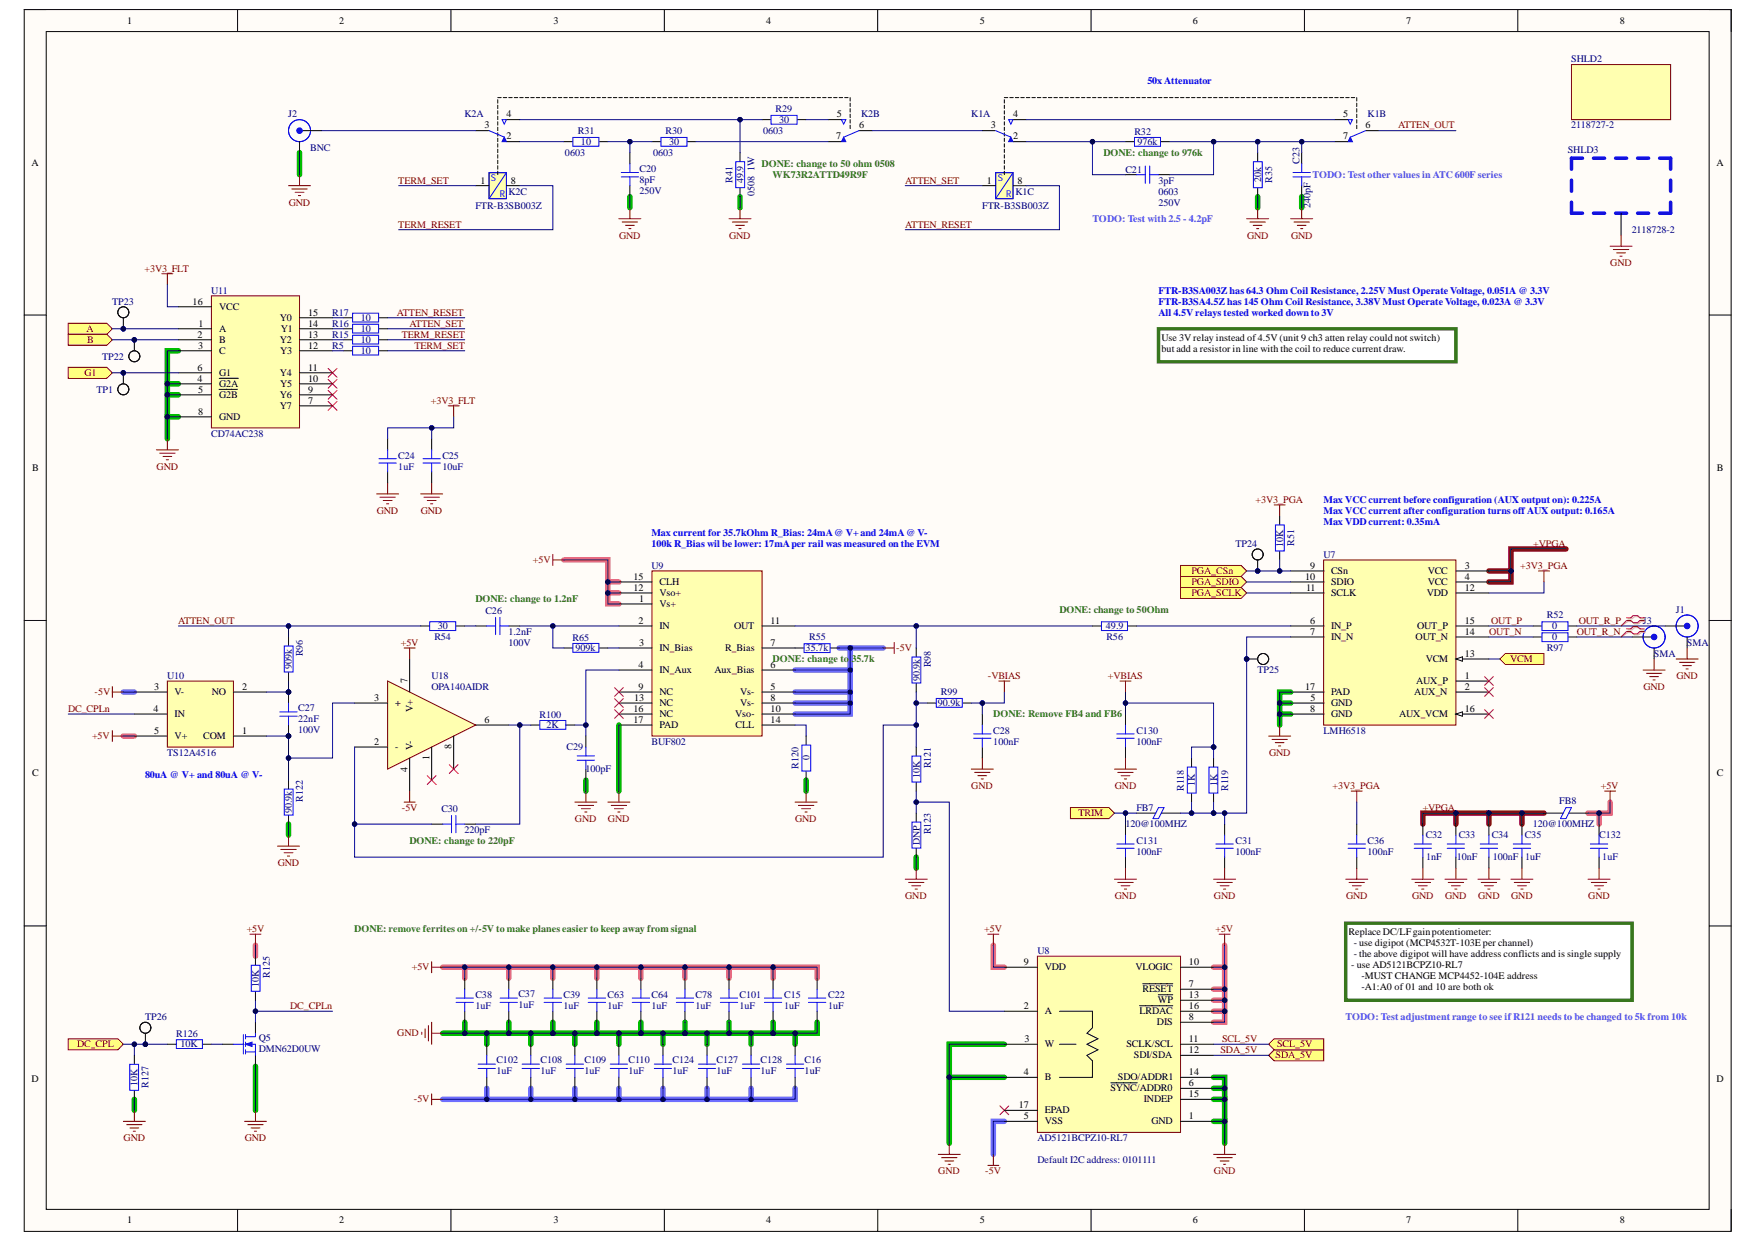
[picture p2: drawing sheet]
<svg xmlns="http://www.w3.org/2000/svg" width="297mm" height="210mm" viewBox="0 0 297 210" stroke-linecap="round" stroke-linejoin="round" font-family="sans-serif">
<defs><g id="words">
<g font-size="1.7">
<text x="21.5" y="4">1</text>
<text x="57.4" y="4">2</text>
<text x="93.6" y="4">3</text>
<text x="129.5" y="4">4</text>
<text x="165.6" y="4">5</text>
<text x="201.7" y="4">6</text>
<text x="237.7" y="4">7</text>
<text x="273.8" y="4">8</text>
<text x="81.9" y="21.7">3</text>
<text x="85.6" y="23.6">2</text>
<text x="85.6" y="19.9">4</text>
<text x="141.4" y="23.6">7</text>
<text x="141.5" y="19.9">5</text>
<text x="145.3" y="21.7">6</text>
<text x="167.5" y="21.7">3</text>
<text x="171.3" y="23.6">2</text>
<text x="171.3" y="19.9">4</text>
<text x="227.1" y="19.9">5</text>
<text x="227.1" y="23.6">7</text>
<text x="230.9" y="21.7">6</text>
<text x="5.3" y="28">A</text>
<text x="290.2" y="28">A</text>
<text x="81.2" y="31">1</text>
<text x="86.4" y="31">8</text>
<text x="166.8" y="31">1</text>
<text x="172" y="31">8</text>
<text x="32.6" y="51.5">16</text>
<text x="37.1" y="52.4">VCC</text>
<text x="52.1" y="53.3">15</text>
<text x="33.4" y="57.1">2</text>
<text x="33.5" y="58.9">3</text>
<text x="33.6" y="55.2">1</text>
<text x="37.1" y="56.1">A</text>
<text x="37.1" y="58">B</text>
<text x="37.1" y="59.8">C</text>
<text x="47.3" y="58">Y2</text>
<text x="47.3" y="54.3">Y0</text>
<text x="47.4" y="59.8">Y3</text>
<text x="47.5" y="56.1">Y1</text>
<text x="52.1" y="58.9">12</text>
<text x="52.1" y="57.1">13</text>
<text x="52.1" y="55.2">14</text>
<text x="196.4" y="57.6">Use 3V relay instead of4.5V (unit 9 ch3 atten relay could not switch)</text>
<text x="196.4" y="59.4">but add a resistor in line with the coil to reduce current draw.</text>
<text x="33.4" y="64.5">4</text>
<text x="33.4" y="62.6">6</text>
<text x="37.1" y="65.4">G2A</text>
<text x="37.1" y="63.6">G1</text>
<text x="47.3" y="63.6">Y4</text>
<text x="47.4" y="65.4">Y5</text>
<text x="52.1" y="64.5">10</text>
<text x="52.1" y="62.6">11</text>
<text x="33.5" y="66.3">5</text>
<text x="33.5" y="70.1">8</text>
<text x="37.1" y="67.3">G2B</text>
<text x="37.1" y="71">GND</text>
<text x="47.3" y="69.1">Y7</text>
<text x="47.3" y="67.3">Y6</text>
<text x="52.1" y="68.2">7</text>
<text x="52.1" y="66.3">9</text>
<text x="5.4" y="79.6">B</text>
<text x="290.3" y="79.6">B</text>
<text x="107.1" y="99.8">12</text>
<text x="107.1" y="98">15</text>
<text x="108" y="101.7">1</text>
<text x="111.5" y="100.8">Vso+</text>
<text x="111.5" y="98.9">CLH</text>
<text x="220.6" y="98">10</text>
<text x="220.8" y="99.8">11</text>
<text x="221.5" y="96.1">9</text>
<text x="225" y="97">CSn</text>
<text x="225" y="98.9">SDIO</text>
<text x="225" y="100.8">SCLK</text>
<text x="241.2" y="100.8">VDD</text>
<text x="241.4" y="97">VCC</text>
<text x="241.4" y="98.9">VCC</text>
<text x="247.6" y="99.8">12</text>
<text x="247.6" y="96.1">3</text>
<text x="247.6" y="98">4</text>
<text x="107.9" y="105.4">2</text>
<text x="111.5" y="102.6">Vs+</text>
<text x="111.5" y="106.3">IN</text>
<text x="124.1" y="106.3">OUT</text>
<text x="130.3" y="105.4">11</text>
<text x="221.5" y="105.4">6</text>
<text x="221.5" y="107.3">7</text>
<text x="225" y="106.3">IN_P</text>
<text x="239.6" y="106.3">OUT_P</text>
<text x="247.6" y="107.3">14</text>
<text x="247.6" y="105.4">15</text>
<text x="107.9" y="112.8">4</text>
<text x="108" y="109.1">3</text>
<text x="111.5" y="110.1">IN_Bias</text>
<text x="111.5" y="113.8">IN_Aux</text>
<text x="120.8" y="113.8">Aux_Bias</text>
<text x="122.6" y="110.1">R_Bias</text>
<text x="130.3" y="112.8">6</text>
<text x="130.3" y="109.1">7</text>
<text x="225" y="108.2">IN_N</text>
<text x="239.3" y="108.2">OUT_N</text>
<text x="241" y="111.9">VCM</text>
<text x="247.6" y="111">13</text>
<text x="26.1" y="116.6">3</text>
<text x="29.5" y="117.5">V-</text>
<text x="35.8" y="117.5">NO</text>
<text x="40.9" y="116.6">2</text>
<text x="63.3" y="118.4">3</text>
<text x="66.8" y="119.4">+</text>
<text x="68.9" y="115.5" transform="rotate(-90 68.9 115.5)">7</text>
<text x="107.2" y="118.4">13</text>
<text x="107.9" y="116.6">9</text>
<text x="111.5" y="117.5">NC</text>
<text x="111.5" y="119.4">NC</text>
<text x="125.1" y="117.5">Vs-</text>
<text x="125.1" y="119.4">Vs-</text>
<text x="130.3" y="116.6">5</text>
<text x="130.3" y="118.4">8</text>
<text x="220.6" y="116.6">17</text>
<text x="221.6" y="118.4">5</text>
<text x="225" y="119.4">GND</text>
<text x="225" y="117.5">PAD</text>
<text x="239.1" y="117.5">AUX_N</text>
<text x="239.4" y="115.6">AUX_P</text>
<text x="247.6" y="114.7">1</text>
<text x="247.6" y="116.6">2</text>
<text x="26" y="120.3">4</text>
<text x="26.1" y="124">5</text>
<text x="29.5" y="124.9">V+</text>
<text x="29.5" y="121.2">IN</text>
<text x="34.3" y="124.9">COM</text>
<text x="40.9" y="124">1</text>
<text x="63.3" y="125.9">2</text>
<text x="69.8" y="120.4" transform="rotate(-90 69.8 120.4)">V+</text>
<text x="81.9" y="122.1">6</text>
<text x="107.1" y="120.3">16</text>
<text x="107.1" y="122.1">17</text>
<text x="111.5" y="121.2">NC</text>
<text x="111.5" y="123.1">PAD</text>
<text x="124.3" y="121.2">Vso-</text>
<text x="124.4" y="123.1">CLL</text>
<text x="130.3" y="120.3">10</text>
<text x="130.3" y="122.1">14</text>
<text x="221.5" y="120.3">8</text>
<text x="225" y="121.2">GND</text>
<text x="236.5" y="121.2">AUX_VCM</text>
<text x="247.6" y="120.3">16</text>
<text x="5.4" y="131.2">C</text>
<text x="66.8" y="126.8">-</text>
<text x="68.9" y="130.4" transform="rotate(-90 68.9 130.4)">4</text>
<text x="69.8" y="126.8" transform="rotate(-90 69.8 126.8)">V-</text>
<text x="72.6" y="128.4" transform="rotate(-90 72.6 128.4)">1</text>
<text x="76.3" y="126.6" transform="rotate(-90 76.3 126.6)">8</text>
<text x="290.3" y="131.2">C</text>
<text x="228" y="158.1">Replace DC/LFgainpotentiometer:</text>
<text x="228.9" y="159.9">- use digipot (MCP4532T-103E per channel)</text>
<text x="228.9" y="161.8">- the above digipot will have address conflicts and is single supply</text>
<text x="173.1" y="163.1">9</text>
<text x="176.6" y="164">VDD</text>
<text x="192" y="164">VLOGIC</text>
<text x="193.1" y="167.7">RESET</text>
<text x="201" y="166.8">7</text>
<text x="201" y="163.1">10</text>
<text x="228.4" y="163.6">- use AD5121BCPZ10-RL7</text>
<text x="230.2" y="165.5">-MUST CHANGE MCP4452-104E address</text>
<text x="230.2" y="167.4">-A1:A0 of 01 and 10 are both ok</text>
<text x="173.1" y="170.5">2</text>
<text x="176.6" y="171.4">A</text>
<text x="192.6" y="171.4">LRDAC</text>
<text x="195.6" y="173.3">DIS</text>
<text x="195.8" y="169.6">WP</text>
<text x="201" y="172.4">8</text>
<text x="201" y="168.6">13</text>
<text x="201" y="170.5">16</text>
<text x="173.2" y="176.1">3</text>
<text x="176.6" y="177">W</text>
<text x="190.4" y="177">SCLK/SCL</text>
<text x="191.7" y="178.9">SDI/SDA</text>
<text x="201" y="176.1">11</text>
<text x="201" y="177.9">12</text>
<text x="5.3" y="182.8">D</text>
<text x="173.1" y="181.7">4</text>
<text x="176.6" y="182.6">B</text>
<text x="187.7" y="184.4">SYNC/ADDR0</text>
<text x="189" y="182.6">SDO/ADDR1</text>
<text x="201" y="183.5">6</text>
<text x="201" y="181.7">14</text>
<text x="201" y="185.4">15</text>
<text x="290.2" y="182.8">D</text>
<text x="172.2" y="187.2">17</text>
<text x="173.1" y="189.1">5</text>
<text x="176.6" y="190">VSS</text>
<text x="176.6" y="188.2">EPAD</text>
<text x="193.4" y="186.3">INDEP</text>
<text x="194.7" y="190">GND</text>
<text x="201" y="189.1">1</text>
<text x="21.5" y="206.8">1</text>
<text x="57.4" y="206.8">2</text>
<text x="93.6" y="206.8">3</text>
<text x="129.5" y="206.8">4</text>
<text x="165.6" y="206.8">5</text>
<text x="201.7" y="206.8">6</text>
<text x="237.7" y="206.8">7</text>
<text x="273.8" y="206.8">8</text>
</g>
<g font-size="1.7" fill="#000080">
<text x="265.6" y="10.6">SHLD2</text>
<text x="48.7" y="19.9">J2</text>
<text x="78.5" y="19.9">K2A</text>
<text x="97.7" y="22.6">R31</text>
<text x="112.5" y="22.6">R30</text>
<text x="129" y="22.6">0603</text>
<text x="131.1" y="18.9">R29</text>
<text x="131.7" y="20.8">30</text>
<text x="145.6" y="19.9">K2B</text>
<text x="164.2" y="19.9">K1A</text>
<text x="191.8" y="22.8">R32</text>
<text x="231.2" y="19.9">K1B</text>
<text x="265.6" y="21.7">2118727-2</text>
<text x="52.5" y="25.4">BNC</text>
<text x="95.5" y="26.4">0603</text>
<text x="98.2" y="24.5">10</text>
<text x="108.1" y="29">C20</text>
<text x="110.4" y="26.4">0603</text>
<text x="113.1" y="24.5">30</text>
<text x="127.6" y="28.9" transform="rotate(-90 127.6 28.9)">1W</text>
<text x="190.3" y="29.2">C21</text>
<text x="192.3" y="24.5">976k</text>
<text x="219.7" y="27.6" transform="rotate(-90 219.7 27.6)">C23</text>
<text x="265.1" y="25.8">SHLD3</text>
<text x="80.4" y="35.2">FTR-B3SB003Z</text>
<text x="86" y="32.9">K2C</text>
<text x="108.1" y="32.7">250V</text>
<text x="108.1" y="30.8">8pF</text>
<text x="123.9" y="30.8" transform="rotate(-90 123.9 30.8)">R41</text>
<text x="125.7" y="30.9" transform="rotate(-90 125.7 30.9)">49.9</text>
<text x="127.6" y="33" transform="rotate(-90 127.6 33)">0508</text>
<text x="166.1" y="35.2">FTR-B3SB003Z</text>
<text x="171.7" y="32.9">K1C</text>
<text x="195.8" y="32.9">0603</text>
<text x="195.8" y="34.7">250V</text>
<text x="195.8" y="31">3pF</text>
<text x="213.2" y="30.8" transform="rotate(-90 213.2 30.8)">20k</text>
<text x="215.1" y="30.8" transform="rotate(-90 215.1 30.8)">R35</text>
<text x="221.6" y="35.1" transform="rotate(-90 221.6 35.1)">240pF</text>
<text x="275.9" y="39.4">2118728-2</text>
<text x="19" y="51.5">TP23</text>
<text x="35.7" y="49.6">U11</text>
<text x="56.2" y="53.3">R17</text>
<text x="56.2" y="58.9">R5</text>
<text x="56.2" y="57.1">R15</text>
<text x="56.2" y="55.2">R16</text>
<text x="61" y="59.8">10</text>
<text x="61" y="58">10</text>
<text x="61" y="56.1">10</text>
<text x="61" y="54.3">10</text>
<text x="17.3" y="60.8">TP22</text>
<text x="16.3" y="66.3">TP1</text>
<text x="35.7" y="73.8">CD74AC238</text>
<text x="67.3" y="77.5">C24</text>
<text x="74.8" y="77.5">C25</text>
<text x="67.3" y="79.4">1uF</text>
<text x="74.8" y="79.4">10uF</text>
<text x="208.9" y="92.4">TP24</text>
<text x="216.9" y="92.4" transform="rotate(-90 216.9 92.4)">10K</text>
<text x="218.8" y="92.2" transform="rotate(-90 218.8 92.2)">R51</text>
<text x="223.8" y="94.2">U7</text>
<text x="110.1" y="96.1">U9</text>
<text x="74" y="106.3">30</text>
<text x="82.1" y="103.7">C26</text>
<text x="86" y="107.3">1.2nF</text>
<text x="187" y="106.3">49.9</text>
<text x="261.5" y="104.5">R52</text>
<text x="262.4" y="106.3">0</text>
<text x="277.7" y="105.4">J3</text>
<text x="283.3" y="103.5">J1</text>
<text x="49.3" y="113.1" transform="rotate(-90 49.3 113.1)">909k</text>
<text x="51.2" y="110.9" transform="rotate(-90 51.2 110.9)">R96</text>
<text x="73.4" y="108.2">R54</text>
<text x="86" y="109.1">100V</text>
<text x="96.8" y="108.4">R65</text>
<text x="97.3" y="110.1">909k</text>
<text x="136.2" y="110.1">35.7k</text>
<text x="136.8" y="108.2">R55</text>
<text x="157.4" y="112.8" transform="rotate(-90 157.4 112.8)">R98</text>
<text x="187" y="108.2">R56</text>
<text x="212.6" y="113.8">TP25</text>
<text x="261.5" y="110.1">R97</text>
<text x="262.4" y="108.2">0</text>
<text x="279.6" y="111">SMA</text>
<text x="285.2" y="109.1">SMA</text>
<text x="28.3" y="114.7">U10</text>
<text x="72.9" y="114.7">U18</text>
<text x="72.9" y="116.6">OPA140AIDR</text>
<text x="155.5" y="115.1" transform="rotate(-90 155.5 115.1)">90.9k</text>
<text x="158.5" y="119.4">90.9k</text>
<text x="159" y="117.5">R99</text>
<text x="50.4" y="123.8">100V</text>
<text x="50.4" y="120.1">C27</text>
<text x="50.4" y="122">22nF</text>
<text x="91.2" y="121.4">R100</text>
<text x="92.4" y="123.1">2K</text>
<text x="110.1" y="125.9">BUF802</text>
<text x="167.9" y="124">C28</text>
<text x="167.9" y="125.9">100nF</text>
<text x="192.1" y="124">C130</text>
<text x="192.1" y="125.9">100nF</text>
<text x="223.8" y="124">LMH6518</text>
<text x="28.3" y="127.7">TS12A4516</text>
<text x="95.8" y="126.8">C29</text>
<text x="99" y="130.5">100pF</text>
<text x="135" y="129.9" transform="rotate(-90 135 129.9)">R120</text>
<text x="136.9" y="128.5" transform="rotate(-90 136.9 128.5)">0</text>
<text x="155.5" y="131.4" transform="rotate(-90 155.5 131.4)">10K</text>
<text x="157.4" y="129.8" transform="rotate(-90 157.4 129.8)">R121</text>
<text x="49.3" y="137.4" transform="rotate(-90 49.3 137.4)">90.9k</text>
<text x="51.2" y="135.5" transform="rotate(-90 51.2 135.5)">R122</text>
<text x="74.6" y="137.3">C30</text>
<text x="192.1" y="137">FB7</text>
<text x="200.2" y="133.6" transform="rotate(-90 200.2 133.6)">R118</text>
<text x="202" y="132.9" transform="rotate(-90 202 132.9)">1K</text>
<text x="205.7" y="132.9" transform="rotate(-90 205.7 132.9)">1K</text>
<text x="207.6" y="133.6" transform="rotate(-90 207.6 133.6)">R119</text>
<text x="263.6" y="135.9">FB8</text>
<text x="78.5" y="140.7">220pF</text>
<text x="155.5" y="142.8" transform="rotate(-90 155.5 142.8)">DNP</text>
<text x="157.4" y="141" transform="rotate(-90 157.4 141)">R123</text>
<text x="190.3" y="139.8">120@100MHZ</text>
<text x="192.1" y="142.6">C131</text>
<text x="208.9" y="142.6">C31</text>
<text x="231.2" y="142.6">C36</text>
<text x="241" y="141.7">C32</text>
<text x="246.6" y="141.7">C33</text>
<text x="252.2" y="141.7">C34</text>
<text x="257.8" y="141.7">C35</text>
<text x="259.1" y="139.8">120@100MHZ</text>
<text x="270.4" y="141.7">C132</text>
<text x="192.1" y="144.5">100nF</text>
<text x="208.9" y="144.5">100nF</text>
<text x="231.2" y="144.5">100nF</text>
<text x="241.1" y="145.4">1nF</text>
<text x="246.3" y="145.4">10nF</text>
<text x="252.4" y="145.4">100nF 1uF</text>
<text x="270.9" y="145.4">1uF</text>
<text x="175.4" y="161.2">U8</text>
<text x="43.7" y="166.8" transform="rotate(-90 43.7 166.8)">10K</text>
<text x="45.6" y="165.3" transform="rotate(-90 45.6 165.3)">R125</text>
<text x="24.5" y="172.4">TP26</text>
<text x="80.4" y="168.6">C38</text>
<text x="80.4" y="170.5">1uF</text>
<text x="87.6" y="168.5">C37</text>
<text x="87.6" y="170.3">1uF</text>
<text x="95.3" y="168.6">C39</text>
<text x="95.3" y="170.5">1uF</text>
<text x="102.7" y="168.6">C63</text>
<text x="102.7" y="170.5">1uF</text>
<text x="110.1" y="168.6">C64</text>
<text x="110.1" y="170.5">1uF</text>
<text x="117.6" y="168.6">C78</text>
<text x="117.6" y="170.5">1uF</text>
<text x="125" y="168.6">C101</text>
<text x="125" y="170.5">1uF</text>
<text x="132.6" y="168.6">C15</text>
<text x="132.6" y="170.5">1uF</text>
<text x="140" y="168.6">C22</text>
<text x="140" y="170.5">1uF</text>
<text x="29.8" y="175.3">R126</text>
<text x="30.5" y="177">10K</text>
<text x="43.7" y="175.9">Q5</text>
<text x="43.7" y="177.8">DMN62D0UW</text>
<text x="83.9" y="179.6">C102</text>
<text x="91.4" y="179.6">C108</text>
<text x="98.8" y="179.6">C109</text>
<text x="106.3" y="179.6">C110</text>
<text x="113.7" y="179.6">C124</text>
<text x="121.1" y="179.6">C127</text>
<text x="128.6" y="179.6">C128</text>
<text x="136" y="179.6">C16</text>
<text x="23.3" y="183.5" transform="rotate(-90 23.3 183.5)">10K</text>
<text x="25.1" y="183.8" transform="rotate(-90 25.1 183.8)">R127</text>
<text x="83.9" y="181.5">1uF</text>
<text x="91.4" y="181.5">1uF</text>
<text x="98.8" y="181.5">1uF</text>
<text x="106.3" y="181.5">1uF</text>
<text x="113.7" y="181.5">1uF</text>
<text x="121.1" y="181.5">1uF</text>
<text x="128.6" y="181.5">1uF</text>
<text x="136" y="181.5">1uF</text>
<text x="175.4" y="192.8">AD5121BCPZ10-RL7</text>
<text x="175.4" y="196.5">Default I2C address: 0101111</text>
</g>
<g font-size="1.7" fill="#00f">
<text x="194" y="14.3">50x Attenuator</text>
<text x="195.8" y="49.6">FTR-B3SA003Z has 64.3 Ohm Coil Resistance, 2.25V Must Operate Voltage, 0.051A @ 3.3V</text>
<text x="195.8" y="51.5">FTR-B3SA4.5Z has 145 Ohm Coil Resistance, 3.38V Must Operate Voltage, 0.023A @ 3.3V</text>
<text x="195.8" y="53.3">All 4.5V relays tested worked down to 3V</text>
<text x="223.8" y="84.9">Max VCC current before configuration (AUX output on): 0.225A</text>
<text x="223.8" y="86.8">Max VCC current after configuration turns offAUX output: 0.165A</text>
<text x="223.8" y="88.7">Max VDD current: 0.35mA</text>
<text x="110.1" y="90.5">Max current for 35.7kOhm R_Bias: 24mA@ V+ and 24mA@ V-</text>
<text x="110.1" y="92.4">100k R_Bias wil be lower: 17mAper rail was measured on the EVM</text>
<text x="24.5" y="131.4">80uA @ V+ and 80uA @ V-</text>
</g>
<g font-size="1.7" fill="#800000">
<text x="236.4" y="21.7">ATTEN_OUT</text>
<text x="48.8" y="34.7">GND</text>
<text x="67.3" y="31">TERM_SET</text>
<text x="153" y="31">ATTEN_SET</text>
<text x="67.3" y="38.5">TERM_RESET</text>
<text x="104.6" y="40.3">GND</text>
<text x="123.3" y="40.3">GND</text>
<text x="153" y="38.5">ATTEN_RESET</text>
<text x="210.8" y="40.3">GND</text>
<text x="218.3" y="40.3">GND</text>
<text x="24.4" y="45.9">+3V3_FLT</text>
<text x="272.2" y="45">GND</text>
<text x="67.1" y="53.3">ATTEN_RESET</text>
<text x="14.6" y="56.1">A</text>
<text x="14.7" y="58">B</text>
<text x="67.9" y="57.1">TERM_RESET</text>
<text x="69.2" y="55.2">ATTEN_SET</text>
<text x="70" y="58.9">TERM_SET</text>
<text x="14.3" y="63.6">G1</text>
<text x="72.8" y="68.2">+3V3_FLT</text>
<text x="26.5" y="79.4">GND</text>
<text x="63.7" y="86.8">GND</text>
<text x="71.1" y="86.8">GND</text>
<text x="212.3" y="84.9">+3V3_PGA</text>
<text x="90.1" y="95.2">+5V</text>
<text x="259.2" y="92.4">+VPGA</text>
<text x="201.4" y="97">PGA_CSn</text>
<text x="201.4" y="100.8">PGA_SCLK</text>
<text x="201.4" y="98.9">PGA_SDIO</text>
<text x="257" y="96.1">+3V3_PGA</text>
<text x="30.1" y="105.4">ATTEN_OUT</text>
<text x="251.8" y="107.3">OUT_N</text>
<text x="252.1" y="105.4">OUT_P</text>
<text x="266.6" y="107.3">OUT_R_N</text>
<text x="266.9" y="105.4">OUT_R_P</text>
<text x="67.8" y="109.1">+5V</text>
<text x="151.5" y="110.1">-5V</text>
<text x="255.3" y="111.9">VCM</text>
<text x="16" y="117.5">-5V</text>
<text x="167" y="114.7">-VBIAS</text>
<text x="187.3" y="114.7">+VBIAS</text>
<text x="277.8" y="116.6">GND</text>
<text x="283.4" y="114.7">GND</text>
<text x="11.5" y="120.3">DC_CPLn</text>
<text x="15.6" y="124.9">+5V</text>
<text x="214.5" y="127.7">GND</text>
<text x="67.9" y="137">-5V</text>
<text x="164.2" y="133.3">GND</text>
<text x="182.3" y="137.9">TRIM</text>
<text x="188.5" y="133.3">GND</text>
<text x="225.3" y="133.3">+3V3_PGA</text>
<text x="240.5" y="137">+VPGA</text>
<text x="270.6" y="133.3">+5V</text>
<text x="97.2" y="138.9">GND</text>
<text x="102.8" y="138.9">GND</text>
<text x="134.4" y="138.9">GND</text>
<text x="47" y="146.3">GND</text>
<text x="153" y="151.9">GND</text>
<text x="188.5" y="151.9">GND</text>
<text x="205.2" y="151.9">GND</text>
<text x="227.6" y="151.9">GND</text>
<text x="238.7" y="151.9">GND</text>
<text x="244.3" y="151.9">GND</text>
<text x="249.9" y="151.9">GND</text>
<text x="255.5" y="151.9">GND</text>
<text x="268.5" y="151.9">GND</text>
<text x="41.7" y="157.5">+5V</text>
<text x="166.4" y="157.5">+5V</text>
<text x="205.5" y="157.5">+5V</text>
<text x="69.6" y="164">+5V</text>
<text x="49.1" y="170.5">DC_CPLn</text>
<text x="13" y="177">DC_CPL</text>
<text x="67.2" y="175.1">GND</text>
<text x="206.3" y="177.9">SDA_5V</text>
<text x="206.6" y="176.1">SCL_5V</text>
<text x="215.6" y="178.9">SDA_5V</text>
<text x="215.9" y="177">SCL_5V</text>
<text x="70" y="186.3">-5V</text>
<text x="20.9" y="192.8">GND</text>
<text x="41.4" y="192.8">GND</text>
<text x="158.6" y="198.4">GND</text>
<text x="166.6" y="198.4">-5V</text>
<text x="205.2" y="198.4">GND</text>
</g>
<g font-size="1.7" fill="#38761d">
<text x="128.8" y="28.2">DONE: change to 50 ohm 0508</text>
<text x="186.5" y="26.4">DONE: change to 976k</text>
<text x="130.6" y="30.1">WK73R2ATTD49R9F</text>
<text x="80.4" y="101.7">DONE: change to 1.2nF</text>
<text x="179.1" y="103.5">DONE: change to 50Ohm</text>
<text x="130.6" y="111.9">DONE: change to 35.7k</text>
<text x="167.9" y="121.2">DONE: Remove FB4 and FB6</text>
<text x="69.2" y="142.6">DONE: change to 220pF</text>
<text x="59.9" y="157.5">DONE: remove ferrites on +/-5V to make planes easier to keep away from signal</text>
</g>
<g font-size="1.7" fill="#90f">
<text x="221.9" y="30.1">TODO: Test other values in ATC 600F series</text>
<text x="184.7" y="37.5">TODO: Test with 2.5 - 4.2pF</text>
<text x="227.5" y="172.4">TODO: Test adjustment range to see ifR121 needs to be changed to 5k from 10k</text>
</g>
<g font-size="1.6" fill="#00f">
<text x="83" y="30.6">S</text>
<text x="84.5" y="33.2">R</text>
<text x="168.7" y="30.6">S</text>
<text x="170.1" y="33.2">R</text>
</g>
</g></defs>
<path d="M4.1 1.6h288.6v206.5h-288.6z" fill-rule="evenodd" fill="#fffcf8"/>
<path d="M4.1 1.6h288.6v206.5h-288.6z" fill="none" stroke="#000" stroke-width=".17"/>
<path d="M7.8 5.3h281.2v199.1h-281.2z" fill-rule="evenodd" fill="#fffcf8"/>
<g fill="none" stroke="#000" stroke-width=".17">
<path d="M4.1 1.6h3.7M7.8 5.3h281.2v199.1h-281.2zM40.2 1.6v3.7M76.2 1.6v3.7M112.3 1.6v3.7M148.4 1.6v3.7M184.5 1.6v3.7M220.5 1.6v3.7M256.6 1.6v3.7M289 1.6h3.7v3.7M274.1 36v3.8M4.1 53.2h3.7"/>
<path d="M289 53.2h3.7M4.1 104.9h3.7M289 104.9h3.7M4.1 156.5h3.7M289 156.5h3.7M40.2 204.4v3.7M76.2 204.4v3.7M112.3 204.4v3.7M148.4 204.4v3.7M184.5 204.4v3.7M220.5 204.4v3.7M256.6 204.4v3.7"/>
<path d="M292.7 204.4v3.7"/>
</g>
<g fill="none" stroke="#00be00" stroke-width=".93">
<path d="M50.6 25.8v3.7M106.5 33.2v1.9M125.1 33.2v1.9M212.6 33.2v1.9M220.1 33.2v1.9M30.2 59.3h-1.9v5.6M28.3 66.7h1.9M30.2 70.4h-1.9v3.8M30.2 64.9h-1.9v5.5M216.3 118.8h1.9M218.2 117h-1.9v3.7h1.9M48.8 139.3v1.8"/>
<path d="M99 131.8v1.9M104.6 122.5v11.2M136.3 131.8v1.9M216.3 120.7v1.8M154.9 144.9v1.8M74.8 174.6h3.8M78.6 172.8v1.8h7.4M82.3 174.6v1.9M86 174.6h7.5M86 172.8v1.8M89.7 174.6v1.9M93.5 174.6h7.4"/>
<path d="M93.5 172.8v1.8M97.2 174.6v1.9M100.9 174.6h7.5M100.9 172.8v1.8M104.6 174.6v1.9M108.4 174.6h7.4M108.4 172.8v1.8M112.1 174.6v1.9M115.8 172.8v1.8M119.5 174.6v1.9M123.3 172.8v1.8h-7.5M123.3 174.6h7.4"/>
<path d="M127 174.6v1.9M130.7 172.8v1.8M134.4 174.6v1.9M138.1 172.8v1.8h-7.4M169.8 176.5h-9.3v16.7M22.7 185.8v1.9M43.2 180.2v7.5M160.5 182.1h9.3M205.2 189.5h1.8v3.7M205.2 185.8h1.8v3.7M205.2 182.1h1.8v3.7M205.2 183.9h1.8"/>
</g>
<path d="M251.7 96.5h3.7M264.7 92.8h-9.3v5.6h-3.7M246.1 137.4h-5.6v1.9M251.7 137.4h-5.6v1.9M257.3 137.4v1.9M261 137.4h-9.3v1.9" fill="none" stroke="#a50021" stroke-width=".93"/>
<g fill="none" stroke="#ff6e6e" stroke-width=".93">
<path d="M95.3 94.6h7.5v7.5h1.8M102.8 98.4h1.8M102.8 100.2h1.8M20.8 124.4h1.9M270.3 137.4v1.9M272.2 135.6v1.8h-3.7M43.2 159.7v1.9M167.9 159.7v3.8h1.9M207 159.7v3.8h-1.8M74.8 163.5h3.8M78.6 165.3v-1.8h37.2v1.8M86 163.5v1.8"/>
<path d="M93.5 163.5v1.8M100.9 163.5v1.8M108.4 163.5v1.8M115.8 163.5h7.4v1.8M123.2 163.5h7.5v1.8M130.7 163.5h7.4v1.8M207 163.5v3.7h-1.8M207 167.2v1.8h-1.8M207 169v1.9h-1.8M207 170.9v1.9h-1.8"/>
</g>
<g fill="none" stroke="#6e6eff" stroke-width=".93">
<path d="M20.8 117h1.9M134.4 113.2h9.3v3.8h-9.3M134.4 118.8h9.3v1.9h-9.3M141.9 109.5h1.8v3.7M143.7 117v1.8M143.7 109.5h5.6M82.3 183.9v1.9M89.7 183.9v1.9M97.2 183.9v1.9M104.6 183.9v1.9M112.1 183.9v1.9M119.5 183.9v1.9"/>
<path d="M127 183.9v1.9M134.4 183.9v1.9h-59.6M169.8 189.5h-1.9v5.6"/>
</g>
<path d="M265.7 30.5v1.8M265.7 34.2v1.8h1.8M267.5 26.7h-1.8v1.9M269.4 36h1.9M269.4 26.7h1.9M273.1 36h1.9M273.1 26.7h1.9M276.9 36h1.8M276.9 26.7h1.8M280.6 26.7h1.8v1.9M282.4 34.2v1.8h-1.8M282.4 30.5v1.8" fill="none" stroke="#00f" stroke-width=".59"/>
<path d="M274.1 39.8v1.8M272.2 41.6h3.7M272.7 42.2h2.7M273.3 42.7h1.5M273.9 43.3h.3" fill="none" stroke="#800000" stroke-width=".17"/>
<path d="M265.7 10.9h16.7v9.3h-16.7z" fill-rule="evenodd" fill="#ffffb0"/>
<path d="M265.7 10.9h16.7v9.3h-16.7zM48.8 31.4h3.7M49.3 31.9h2.6M49.9 32.5h1.5M50.5 33.1h.3M50.6 29.5v1.9" fill="none" stroke="#800000" stroke-width=".17"/>
<circle cx="50.6" cy="22.1" r="1.86" fill="none" stroke="#00f" stroke-width=".17"/>
<path d="M50.6 22.1h3.8M50.6 23.9v1.9" fill="none" stroke="#000" stroke-width=".17"/>
<circle cx="50.6" cy="22.1" r=".46" fill="#00f"/>
<g fill="none" stroke="#00f" stroke-width=".17">
<path d="M186.2 105.1h4.4v1.5h-4.4z"/>
<circle cx="50.6" cy="22.1" r=".46"/>
</g>
<path d="M184.7 105.8h1.5M190.7 105.8h1.4" fill="none" stroke="#000" stroke-width=".17"/>
<path d="M223.8 94.6h22.3v27.9h-22.3z" fill-rule="evenodd" fill="#ffffb0"/>
<path d="M223.8 94.6h22.3v27.9h-22.3z" fill="none" stroke="#800000" stroke-width=".17"/>
<path d="M218.2 96.5h5.6M218.2 98.4h5.6M218.2 100.2h5.6M246.1 100.2h5.6M246.1 111.4h5.6" fill="none" stroke="#000" stroke-width=".17"/>
<path d="M246.1 111.4l1.1-.4v.8z" fill="#f8fcff"/>
<path d="M246.1 111.4l1.1-.4v.8zM246.1 107.7h5.6M246.1 105.8h5.6M246.1 115.1h5.6M246.1 117h5.6M246.1 120.7h5.6" fill="none" stroke="#000" stroke-width=".17"/>
<path d="M246.1 120.7l1.1-.4v.8z" fill="#f8fcff"/>
<path d="M246.1 96.5h5.6M246.1 98.4h5.6M218.2 118.8h5.6M218.2 117h5.6M218.2 105.8h5.6M218.2 107.7h5.6M218.2 120.7h5.6M246.1 120.7l1.1-.4v.8z" fill="none" stroke="#000" stroke-width=".17"/>
<path d="M199.6 95.6h10.2l1 .9-1 .9h-10.2z" fill-rule="evenodd" fill="#ffff80"/>
<path d="M199.6 95.6h10.2l1 .9-1 .9h-10.2z" fill="none" stroke="#800000" stroke-width=".17"/>
<path d="M216.3 87.2v1.5M216.3 93.2v1.4" fill="none" stroke="#000" stroke-width=".17"/>
<path d="M215.6 88.7h1.5v4.4h-1.5z" fill="none" stroke="#00f" stroke-width=".17"/>
<path d="M199.6 99.3h10.2l1 .9-1 .9h-10.2z" fill-rule="evenodd" fill="#ffff80"/>
<path d="M199.6 99.3h10.2l1 .9-1 .9h-10.2z" fill="none" stroke="#800000" stroke-width=".17"/>
<path d="M199.6 97.4h10.2l1 1-1 .9h-10.2z" fill-rule="evenodd" fill="#ffff80"/>
<path d="M199.6 97.4h10.2l1 1-1 .9h-10.2zM214.5 124.4h3.7M215 125h2.6M215.6 125.5h1.5M216.2 126.1h.3M216.3 122.5v1.9" fill="none" stroke="#800000" stroke-width=".17"/>
<path d="M253.6 111.4l.9-1h6.5v1.9h-6.5z" fill-rule="evenodd" fill="#ffff80"/>
<path d="M253.6 111.4l.9-1h6.5v1.9h-6.5z" fill="none" stroke="#800000" stroke-width=".17"/>
<path d="M251 114.4l1.5 1.4M251 116.2l1.5 1.5M251 119.9l1.5 1.5M252.5 114.4l-1.5 1.4M252.5 116.2l-1.5 1.5M252.5 119.9l-1.5 1.5" fill="none" stroke="#f00" stroke-width=".17"/>
<path d="M259.2 105.8h1.4M259.2 107.7h1.4M265.1 105.8h1.5M265.1 107.7h1.5" fill="none" stroke="#000" stroke-width=".17"/>
<path d="M260.7 105.1h4.4v1.5h-4.4zM260.7 106.9h4.4v1.5h-4.4z" fill="none" stroke="#00f" stroke-width=".17"/>
<circle cx="212.6" cy="96.5" r=".37" fill="#000080"/>
<circle cx="212.6" cy="96.5" r=".37" fill="none" stroke="#000080" stroke-width=".17"/>
<path d="M212.6 94.6v1.9" fill="none" stroke="#000" stroke-width=".17"/>
<circle cx="212.6" cy="96.5" r=".37" fill="#000080"/>
<circle cx="212.6" cy="96.5" r=".37" fill="none" stroke="#000080" stroke-width=".17"/>
<g fill="none" stroke="#000" stroke-width=".17">
<path d="M201.4 128.1v1.5M201.4 134.1v1.5M205.2 128.1v1.5M205.2 134.1v1.5M229.4 139.3v1.8M240.5 139.3v1.8M246.1 139.3v1.8M251.7 139.3v1.8M257.3 139.3v1.8M229.4 144.9v1.8M240.5 144.9v1.8M246.1 144.9v1.8"/>
<path d="M251.7 144.9v1.8M257.3 144.9v1.8"/>
<circle cx="212.6" cy="93.7" r=".93"/>
</g>
<g fill="none" stroke="#00f" stroke-width=".17">
<path d="M200.7 129.6h1.5v4.4h-1.5zM204.4 129.6h1.5v4.4h-1.5zM227.9 143.4h2.9M227.9 142.6h2.9M229.4 141.1v1.5M229.4 143.4v1.5M239.1 143.4h2.9M239.1 142.6h2.9M240.5 141.1v1.5M240.5 143.4v1.5M244.7 143.4h2.9M244.7 142.6h2.9"/>
<path d="M246.1 141.1v1.5M246.1 143.4v1.5M250.2 143.4h3M250.2 142.6h3M251.7 141.1v1.5M251.7 143.4v1.5M255.8 143.4h3M255.8 142.6h3M257.3 141.1v1.5M257.3 143.4v1.5"/>
</g>
<g fill="none" stroke="#800000" stroke-width=".17">
<path d="M271.3 133.7h1.8M272.2 133.7v1.9M227.5 148.6h3.7M228.1 149.1h2.6M228.6 149.7h1.5M229.2 150.3h.4M229.4 146.7v1.9M238.7 148.6h3.7M239.2 149.1h2.6M239.8 149.7h1.5M240.4 150.3h.3M240.5 146.7v1.9"/>
<path d="M244.3 148.6h3.7M244.8 149.1h2.6M245.4 149.7h1.5M245.9 150.3h.4M246.1 146.7v1.9M249.9 148.6h3.7M250.4 149.1h2.6M251 149.7h1.5M251.5 150.3h.4M251.7 146.7v1.9M255.4 148.6h3.8M256 149.1h2.6"/>
<path d="M256.6 149.7h1.5M257.1 150.3h.4M257.3 146.7v1.9"/>
</g>
<path d="M181 136.5h6.5l.9 .9-.9 .9h-6.5z" fill-rule="evenodd" fill="#ffff80"/>
<path d="M181 136.5h6.5l.9 .9-.9 .9h-6.5z" fill="none" stroke="#800000" stroke-width=".17"/>
<circle cx="210.8" cy="111.4" r=".38" fill="#000080"/>
<circle cx="210.8" cy="111.4" r=".38" fill="none" stroke="#000080" stroke-width=".17"/>
<path d="M210.8 111.4h1.8" fill="none" stroke="#000" stroke-width=".17"/>
<circle cx="210.8" cy="111.4" r=".38" fill="#000080"/>
<circle cx="210.8" cy="111.4" r=".38" fill="none" stroke="#000080" stroke-width=".17"/>
<g fill="none" stroke="#000" stroke-width=".17">
<path d="M207 139.3v1.8M207 144.9v1.8"/>
<circle cx="213.5" cy="111.4" r=".93"/>
<circle cx="213.6" cy="111.4" r=".93"/>
</g>
<path d="M205.6 142.6h2.9M205.6 143.4h2.9M207 141.1v1.5M207 143.4v1.5" fill="none" stroke="#00f" stroke-width=".17"/>
<path d="M215.4 85.3h1.9M216.3 85.3v1.9M260.1 96.5h1.9M261 96.5v1.9M228.4 133.7h1.9M229.4 133.7v1.9M205.2 148.6h3.7M205.7 149.1h2.6M206.3 149.7h1.5M206.8 150.3h.4M207 146.7v1.9" fill="none" stroke="#800000" stroke-width=".17"/>
<path d="M168.3 29.2h3v4.4h-3z" fill-rule="evenodd" fill="#ffffb0"/>
<path d="M168.3 29.2h3v4.4h-3z" fill="none" stroke="#800000" stroke-width=".17"/>
<path d="M171.3 29.2l-3 4.4M171.3 29.2h-3v4.4M171.3 29.2v4.4h-3" fill="none" stroke="#00f" stroke-width=".17"/>
<path d="M166.1 31.4h2.2M171.3 31.4h2.2" fill="none" stroke="#000" stroke-width=".17"/>
<path d="M11.5 56.5h6.6l.9 .9-.9 1h-6.6z" fill-rule="evenodd" fill="#ffff80"/>
<path d="M210.8 37h3.7M211.3 37.5h2.6M211.9 38.1h1.5M212.4 38.6h.4M212.6 35.1v1.9M218.2 37h3.7M218.8 37.5h2.6M219.3 38.1h1.5M219.9 38.6h.4M220.1 35.1v1.9M11.5 56.5h6.6l.9 .9-.9 1h-6.6z" fill="none" stroke="#800000" stroke-width=".17"/>
<g fill="none" stroke="#000" stroke-width=".17">
<path d="M169.8 16.8v.6M169.8 17.8v.6M169.8 18.7v.6M169.8 19.6v.6M169.8 16.5h.6M170.7 16.5h.6M171.7 16.5h.5M172.6 16.5h.6M173.5 16.5h.6M174.5 16.5h.5M175.4 16.5h.6M176.3 16.5h.6"/>
<path d="M177.2 16.5h.6M178.2 16.5h.6M179.1 16.5h.6M180 16.5h.6M181 16.5h.6M181.9 16.5h.6M182.8 16.5h.6M183.8 16.5h.5M184.7 16.5h.6M185.6 16.5h.6M186.6 16.5h.5M187.5 16.5h.6"/>
<path d="M188.4 16.5h.6M189.3 16.5h.6M190.3 16.5h.6M191.2 16.5h.6M192.1 16.5h.6M193.1 16.5h.5M194 16.5h.6M194.9 16.5h.6M195.9 16.5h.5M196.8 16.5h.6M197.7 16.5h.6M198.7 16.5h.5"/>
<path d="M199.6 16.5h.6M200.5 16.5h.6M201.4 16.5h.6M202.4 16.5h.6M203.3 16.5h.6M204.2 16.5h.6M205.2 16.5h.5M206.1 16.5h.6M207 16.5h.6M208 16.5h.5M208.9 16.5h.6M209.8 16.5h.6"/>
<path d="M210.8 16.5h.5M211.7 16.5h.6M212.6 16.5h.6M213.6 16.5h.5M214.5 16.5h.6M215.4 16.5h.6M216.3 16.5h.6M217.3 16.5h.6M218.2 16.5h.6M219.1 16.5h.6M220.1 16.5h.5M221 16.5h.6"/>
<path d="M221.9 16.5h.6M222.9 16.5h.5M223.8 16.5h.6M224.7 16.5h.6M225.6 16.5h.6M226.6 16.5h.6M227.5 16.5h.6M228.4 16.5h.6M229.4 16.5v.6M229.4 17.4v.6M229.4 18.4v.5M229.4 19.3v.6"/>
<path d="M166.1 22.1h2.2M169.8 20.6v.6M169.8 21.5v.6M169.8 22.4v.6M169.8 23.4v.5M169.8 24.3v.6M169.8 25.2v.6M169.8 26.1v.6M169.8 27.1v.6M169.8 28v.6M169.8 28.9v.6M190.3 23.9h1.4"/>
<path d="M190.3 29.5h1.8M195.9 29.5h1.8M196.3 23.9h1.4M212.6 25.8v1.5M212.6 31.8v1.4M220.1 25.8v1.9M220.1 31.4v1.8M229.4 20.2v.6M229.4 21.2v.5"/>
</g>
<path d="M168.3 22.1l2.6 1.1M191.8 23.2h4.4v1.5h-4.4zM192.1 29.5h1.5M193.6 28.1v2.9M194.4 29.5h1.5M194.4 28.1v2.9M211.9 27.3h1.5v4.4h-1.5zM218.6 29.9h2.9M218.6 29.2h2.9M220.1 27.7v1.5M220.1 29.9v1.5" fill="none" stroke="#00f" stroke-width=".17"/>
<path d="M170.9 23.2l.4 .7h-.8z" fill="#00f"/>
<path d="M170.5 20.2h.8l-.4 .8zM170.9 23.2l.4 .7h-.8zM227.9 20.2h.7l-.3 .8zM230.9 22.1l-2.6 1.1" fill="none" stroke="#00f" stroke-width=".17"/>
<path d="M171.3 23.9h2.2M171.3 20.2h2.2M230.9 22.1h2.2" fill="none" stroke="#000" stroke-width=".17"/>
<path d="M228.3 23.2l.3 .7h-.7z" fill="#00f"/>
<path d="M228.3 23.2l.3 .7h-.7z" fill="none" stroke="#00f" stroke-width=".17"/>
<path d="M225.6 20.2h2.2M225.6 23.9h2.2" fill="none" stroke="#000" stroke-width=".17"/>
<path d="M11.5 54.6h6.6l.9 1-.9 .9h-6.6z" fill-rule="evenodd" fill="#ffff80"/>
<path d="M104.6 37h3.8M105.2 37.5h2.6M105.7 38.1h1.5M106.3 38.6h.4M106.5 35.1v1.9M11.5 54.6h6.6l.9 1-.9 .9h-6.6z" fill="none" stroke="#800000" stroke-width=".17"/>
<path d="M106.5 25.8v1.9M106.5 31.4v1.8" fill="none" stroke="#000" stroke-width=".17"/>
<path d="M105 29.2h3M105 29.9h3M106.5 27.7v1.5M106.5 29.9v1.5" fill="none" stroke="#00f" stroke-width=".17"/>
<path d="M82.7 29.2h2.9v4.4h-2.9z" fill-rule="evenodd" fill="#ffffb0"/>
<path d="M82.7 29.2h2.9v4.4h-2.9z" fill="none" stroke="#800000" stroke-width=".17"/>
<path d="M82.7 22.1l2.6 1.1M85.6 29.2l-2.9 4.4M85.6 29.2h-2.9v4.4M85.6 29.2v4.4h-2.9" fill="none" stroke="#00f" stroke-width=".17"/>
<g fill="none" stroke="#000" stroke-width=".17">
<path d="M84.2 16.8v.6M84.2 17.8v.6M84.2 18.7v.6M84.2 19.6v.6M84.2 16.5h.5M85.1 16.5h.6M86 16.5h.6M86.9 16.5h.6M87.9 16.5h.6M88.8 16.5h.6M89.7 16.5h.6M90.7 16.5h.5"/>
<path d="M91.6 16.5h.6M92.5 16.5h.6M93.5 16.5h.5M94.4 16.5h.6M95.3 16.5h.6M96.3 16.5h.5M97.2 16.5h.6M98.1 16.5h.6M99 16.5h.6M100 16.5h.6M100.9 16.5h.6M101.8 16.5h.6"/>
<path d="M102.8 16.5h.5M103.7 16.5h.6M104.6 16.5h.6M105.6 16.5h.5M106.5 16.5h.6M107.4 16.5h.6M108.4 16.5h.5M109.3 16.5h.6M110.2 16.5h.6M111.1 16.5h.6M112.1 16.5h.6M113 16.5h.6"/>
<path d="M113.9 16.5h.6M114.9 16.5h.6M115.8 16.5h.6M116.7 16.5h.6M117.7 16.5h.5M118.6 16.5h.6M119.5 16.5h.6M120.5 16.5h.5M121.4 16.5h.6M122.3 16.5h.6M123.2 16.5h.6M124.2 16.5h.6"/>
<path d="M125.1 16.5h.6M126 16.5h.6M127 16.5h.6M127.9 16.5h.6M128.8 16.5h.6M129.8 16.5h.5M130.7 16.5h.6M131.6 16.5h.6M132.6 16.5h.5M133.5 16.5h.6M134.4 16.5h.6M135.3 16.5h.6"/>
<path d="M136.3 16.5h.6M137.2 16.5h.6M138.1 16.5h.6M139.1 16.5h.6M140 16.5h.6M140.9 16.5h.6M141.9 16.5h.5M142.8 16.5h.6M143.7 16.5v.6M143.7 17.4v.6M143.7 18.4v.5M143.7 19.3v.6"/>
<path d="M80.4 31.4h2.2M80.4 22.1h2.2M84.2 20.6v.6M84.2 21.5v.6M84.2 22.4v.6M84.2 23.4v.5M84.2 24.3v.6M84.2 25.2v.6M84.2 26.1v.6M84.2 27.1v.6M84.2 28v.6M84.2 28.9v.6"/>
<path d="M85.7 31.4h2.2M143.7 20.2v.6M143.7 21.2v.5"/>
</g>
<path d="M85.3 23.2l.3 .7h-.7z" fill="#00f"/>
<path d="M84.9 20.2h.7l-.3 .8zM85.3 23.2l.3 .7h-.7zM142.3 20.2h.7l-.4 .8zM145.2 22.1l-2.5 1.1" fill="none" stroke="#00f" stroke-width=".17"/>
<path d="M85.7 23.9h2.2M85.7 20.2h2.2M145.3 22.1h2.2" fill="none" stroke="#000" stroke-width=".17"/>
<path d="M142.6 23.2l.4 .7h-.7z" fill="#00f"/>
<path d="M130.4 19.5h4.4v1.5h-4.4zM96.8 23.2h4.4v1.5h-4.4zM124.4 27.3h1.5v4.4h-1.5zM142.6 23.2l.4 .7h-.7z" fill="none" stroke="#00f" stroke-width=".17"/>
<path d="M95.3 23.9h1.5M101.3 23.9h1.5M125.1 25.8v1.5M125.1 31.8v1.4M128.8 20.2h1.5M134.8 20.2h1.5M140 20.2h2.2M140 23.9h2.2" fill="none" stroke="#000" stroke-width=".17"/>
<path d="M123.2 37h3.8M123.8 37.5h2.6M124.4 38.1h1.5M124.9 38.6h.4M125.1 35.1v1.9M46.9 143h3.7M47.5 143.6h2.6M48 144.1h1.5M48.6 144.7h.4M48.8 141.1v1.9" fill="none" stroke="#800000" stroke-width=".17"/>
<path d="M65.5 115.1l14.9 7.4-14.9 7.5z" fill="#ffffb0"/>
<g fill="none" stroke="#800000" stroke-width=".17">
<path d="M65.5 115.1l14.9 7.4-14.9 7.5zM168.9 115.1h1.8M169.8 115.1v1.9M164.2 130h3.7M164.8 130.5h2.6M165.3 131.1h1.5M165.9 131.6h.4M166.1 128.1v1.9M153 148.6h3.8M153.6 149.1h2.6M154.2 149.7h1.4M154.7 150.3h.4"/>
<path d="M154.9 146.7v1.9"/>
</g>
<g fill="none" stroke="#000" stroke-width=".17">
<path d="M48.8 107.7v1.4M48.8 113.6v1.5M59.9 118.8h5.6M69.3 111.4v5.6M71.1 105.8h1.5M77.1 105.8h1.5M80.4 105.8h1.9M86 105.8h1.9M154.9 109.5v1.5M154.9 115.5v1.5M156.8 118.8h1.4M162.7 118.8h1.5"/>
<path d="M48.8 131.8v1.5M48.8 137.8v1.5M59.9 126.3h5.6M69.3 128.1v5.6M73 126.3v5.5M73 139.3h1.8M76.7 124.4v5.6M78.6 139.3h1.8M80.4 122.5h5.6M89.7 122.5h1.5M95.7 122.5h1.5M154.9 126.3v1.4"/>
<path d="M154.9 132.2v1.5M154.9 137.4v1.5M166.1 120.7v1.8M166.1 126.3v1.8M154.9 143.4v1.5M78.6 165.3v1.9M78.6 170.9v1.9M93.5 165.3v1.9M93.5 170.9v1.9M100.9 165.3v1.9M100.9 170.9v1.9M108.4 165.3v1.9"/>
<path d="M108.4 170.9v1.9M115.8 165.3v1.9M115.8 170.9v1.9"/>
</g>
<path d="M72.2 131.1l1.5 1.5M73.7 131.1l-1.5 1.5M76 129.2l1.4 1.5M77.4 129.2l-1.4 1.5" fill="none" stroke="#f00" stroke-width=".17"/>
<g fill="none" stroke="#00f" stroke-width=".17">
<path d="M48.1 109.2h1.4v4.4h-1.4zM72.6 105.1h4.4v1.5h-4.4zM82.3 105.8h1.5M83.8 104.3v3M84.5 105.8h1.5M84.5 104.3v3M154.2 111h1.5v4.4h-1.5zM158.3 118h4.4v1.5h-4.4zM48.1 133.4h1.4v4.4h-1.4zM74.8 139.3h1.5M76.3 137.8v2.9M77.1 139.3h1.5"/>
<path d="M77.1 137.8v2.9M91.3 121.8h4.4v1.4h-4.4zM154.2 127.8h1.5v4.4h-1.5zM154.2 138.9h1.5v4.4h-1.5zM164.6 124h2.9M164.6 124.8h2.9M166.1 122.5v1.5M166.1 124.8v1.5M77.1 168.7h2.9M77.1 169.4h2.9M78.6 167.2v1.5M78.6 169.4v1.5"/>
<path d="M92 168.7h2.9M92 169.4h2.9M93.5 167.2v1.5M93.5 169.4v1.5M99.4 168.7h3M99.4 169.4h3M100.9 167.2v1.5M100.9 169.4v1.5M106.9 168.7h2.9M106.9 169.4h2.9M108.4 167.2v1.5M108.4 169.4v1.5"/>
<path d="M114.3 168.7h3M114.3 169.4h3M115.8 167.2v1.5M115.8 169.4v1.5"/>
</g>
<path d="M110.2 96.5h18.6v27.9h-18.6z" fill-rule="evenodd" fill="#ffffb0"/>
<g fill="none" stroke="#800000" stroke-width=".17">
<path d="M110.2 96.5h18.6v27.9h-18.6zM97.2 135.6h3.7M97.7 136.1h2.6M98.3 136.7h1.5M98.9 137.2h.3M99 133.7v1.9M102.8 135.6h3.7M103.3 136.1h2.6M103.9 136.7h1.5M104.4 137.2h.4M104.6 133.7v1.9M134.4 135.6h3.7"/>
<path d="M135 136.1h2.6M135.5 136.7h1.5M136.1 137.2h.4M136.3 133.7v1.9M71.3 174.4v.4M71.9 173.9v1.5M72.4 173.3v2.6M73 162.5v1.9M73 172.8v3.7M73 163.5h1.8M73 174.6h1.8M73 184.9v1.8"/>
<path d="M73 185.8h1.8"/>
</g>
<g fill="none" stroke="#000" stroke-width=".17">
<path d="M104.6 98.4h5.6M95.3 109.5h1.5M101.3 109.5h1.5M104.6 102.1h5.6M104.6 105.8h5.6M104.6 109.5h5.6M104.6 113.2h5.6M104.6 117h5.6M104.6 118.8h5.6M104.6 100.2h5.6M128.8 105.8h5.6M128.8 109.5h7.1"/>
<path d="M128.8 113.2h5.6M128.8 117h5.6M128.8 118.8h5.6M140.4 109.5h1.5M99 124.4v1.9M99 130v1.8M104.6 120.7h5.6M104.6 122.5h5.6M128.8 120.7h5.6M128.8 122.5h5.6M136.3 124.4v1.5M136.3 130.4v1.4"/>
<path d="M43.2 161.6v1.5M43.2 167.6v1.4M86 165.3v1.9M86 170.9v1.9M89.7 176.5v1.9M97.2 176.5v1.9M104.6 176.5v1.9M112.1 176.5v1.9M89.7 182.1v1.8M97.2 182.1v1.8M104.6 182.1v1.8M112.1 182.1v1.8"/>
</g>
<path d="M103.9 116.2l1.5 1.5M103.9 118.1l1.5 1.5M103.9 119.9l1.5 1.5M105.4 116.2l-1.5 1.5M105.4 118.1l-1.5 1.5M105.4 119.9l-1.5 1.5" fill="none" stroke="#f00" stroke-width=".17"/>
<g fill="none" stroke="#00f" stroke-width=".17">
<path d="M96.8 108.7h4.4v1.5h-4.4zM135.9 108.8h4.4v1.5h-4.4zM97.6 128.5h2.9M97.6 127.8h2.9M99 126.3v1.5M99 128.5v1.5M135.6 125.9h1.5v4.4h-1.5zM42.5 163.1h1.5v4.4h-1.5zM84.5 169.4h3M84.5 168.7h3M86 167.2v1.5M86 169.4v1.5"/>
<path d="M88.3 179.8h2.9M89.7 178.4v1.4M95.7 179.8h3M97.2 178.4v1.4M103.2 179.8h2.9M104.6 178.4v1.4M110.6 179.8h2.9M112.1 178.4v1.4M88.3 180.6h2.9M89.7 180.6v1.5M95.7 180.6h3M97.2 180.6v1.5"/>
<path d="M103.2 180.6h2.9M104.6 180.6v1.5M110.6 180.6h2.9M112.1 180.6v1.5"/>
</g>
<circle cx="24.6" cy="176.5" r=".37" fill="#000080"/>
<circle cx="24.6" cy="176.5" r=".37" fill="none" stroke="#000080" stroke-width=".17"/>
<path d="M24.6 174.6v1.9" fill="none" stroke="#000" stroke-width=".17"/>
<circle cx="24.6" cy="176.5" r=".37" fill="#000080"/>
<circle cx="24.6" cy="176.5" r=".37" fill="none" stroke="#000080" stroke-width=".17"/>
<g fill="none" stroke="#000" stroke-width=".17">
<path d="M22.7 178.4v1.4M22.7 184.3v1.5"/>
<circle cx="24.6" cy="173.7" r=".93"/>
</g>
<path d="M21.9 179.9h1.5v4.4h-1.5z" fill="none" stroke="#00f" stroke-width=".17"/>
<path d="M20.9 189.5h3.7M21.4 190.1h2.6M22 190.6h1.5M22.5 191.2h.4M22.7 187.7v1.8" fill="none" stroke="#800000" stroke-width=".17"/>
<path d="M11.5 175.6h8.4l1 .9-1 .9h-8.4z" fill-rule="evenodd" fill="#ffff80"/>
<path d="M11.5 175.6h8.4l1 .9-1 .9h-8.4z" fill="none" stroke="#800000" stroke-width=".17"/>
<path d="M82.3 176.5v1.9M119.5 176.5v1.9M123.2 165.3v1.9M123.2 170.9v1.9M127 176.5v1.9M82.3 182.1v1.8M119.5 182.1v1.8M127 182.1v1.8" fill="none" stroke="#000" stroke-width=".17"/>
<g fill="none" stroke="#00f" stroke-width=".17">
<path d="M80.8 179.8h3M82.3 178.4v1.4M118.1 179.8h2.9M119.5 178.4v1.4M121.8 169.4h2.9M121.8 168.7h2.9M123.2 167.2v1.5M123.2 169.4v1.5M125.5 179.8h2.9M127 178.4v1.4M80.8 180.6h3M82.3 180.6v1.5"/>
<path d="M118.1 180.6h2.9M119.5 180.6v1.5M125.5 180.6h2.9M127 180.6v1.5"/>
</g>
<path d="M28.3 115.1h11.2v11.2h-11.2z" fill-rule="evenodd" fill="#ffffb0"/>
<path d="M28.3 115.1h11.2v11.2h-11.2z" fill="none" stroke="#800000" stroke-width=".17"/>
<path d="M22.7 117h5.6M39.5 117h5.5M22.7 124.4h5.6M22.7 120.7h5.6M39.5 124.4h5.5" fill="none" stroke="#000" stroke-width=".17"/>
<circle cx="48.8" cy="117" r=".37" fill="#000080"/>
<circle cx="48.8" cy="117" r=".37" fill="none" stroke="#000080" stroke-width=".17"/>
<circle cx="48.8" cy="124.4" r=".37" fill="#000080"/>
<circle cx="48.8" cy="124.4" r=".37" fill="none" stroke="#000080" stroke-width=".17"/>
<path d="M48.8 117v1.8" fill="none" stroke="#000" stroke-width=".17"/>
<circle cx="48.8" cy="117" r=".37" fill="#000080"/>
<circle cx="48.8" cy="117" r=".37" fill="none" stroke="#000080" stroke-width=".17"/>
<path d="M48.8 122.5v1.9" fill="none" stroke="#000" stroke-width=".17"/>
<circle cx="48.8" cy="124.4" r=".37" fill="#000080"/>
<circle cx="48.8" cy="124.4" r=".37" fill="none" stroke="#000080" stroke-width=".17"/>
<path d="M48.8 118.8v1.5M47.3 120.3h2.9M47.3 121h2.9M48.8 121v1.5M39.5 176.5h1.6M41.1 174.8v3.3M41.5 175.2h1.7M41.5 176.5h1.7v1.9M41.5 177.8h1.7M41.5 174.8v.8M41.5 176.1v.8M41.5 177.4v.7" fill="none" stroke="#00f" stroke-width=".17"/>
<path d="M37.6 176.5h1.9M43.2 172.8v1.8M43.2 178.4v1.8" fill="none" stroke="#000" stroke-width=".17"/>
<path d="M41.5 176.5l1.1-.4v.8z" fill="#00f"/>
<g fill="none" stroke="#00f" stroke-width=".17">
<path d="M188.8 124h2.9M188.8 124.8h2.9M190.3 122.5v1.5M190.3 124.8v1.5M195.9 136.5h.9l-.9 1.8h-1zM264.7 136.5h1l-1 1.8h-.9zM188.8 142.6h2.9M188.8 143.4h2.9M190.3 141.1v1.5M190.3 143.4v1.5M268.9 142.6h2.9M268.9 143.4h2.9"/>
<path d="M270.3 141.1v1.5M270.3 143.4v1.5M29.8 175.7h4.4v1.5h-4.4zM41.5 176.5l1.1-.4v.8zM43.2 174.6v.6"/>
<circle cx="279.6" cy="107.7" r="1.86"/>
</g>
<g fill="none" stroke="#800000" stroke-width=".17">
<path d="M189.3 115.1h1.9M190.3 115.1v1.9M188.4 130h3.7M189 130.5h2.6M189.5 131.1h1.5M190.1 131.6h.4M190.3 128.1v1.9M188.4 148.6h3.7M189 149.1h2.6M189.5 149.7h1.5M190.1 150.3h.4M190.3 146.7v1.9"/>
<path d="M268.5 148.6h3.7M269 149.1h2.6M269.6 149.7h1.5M270.1 150.3h.4M270.3 146.7v1.9M41.3 189.5h3.7M41.9 190.1h2.6M42.4 190.6h1.5M43 191.2h.4M43.2 187.7v1.8"/>
</g>
<g fill="none" stroke="#000" stroke-width=".17">
<path d="M275.9 107.7h3.7M279.6 109.5v1.9M190.3 120.7v1.8M190.3 126.3v1.8M190.3 139.3v1.8M192.1 137.4h3.3M196.3 137.4h3.3M261 137.4h3.3M265.2 137.4h3.3M270.3 139.3v1.8M190.3 144.9v1.8M270.3 144.9v1.8"/>
<path d="M28.3 176.5h1.5M34.3 176.5h1.4"/>
</g>
<circle cx="279.6" cy="107.7" r=".46" fill="#00f"/>
<g fill="none" stroke="#00f" stroke-width=".17">
<circle cx="279.6" cy="107.7" r=".46"/>
<circle cx="285.2" cy="105.8" r="1.86"/>
</g>
<path d="M277.8 113.2h3.7M278.3 113.8h2.6M278.9 114.4h1.5M279.5 114.9h.3M279.6 111.4v1.8" fill="none" stroke="#800000" stroke-width=".17"/>
<path d="M281.5 105.8h3.7M285.2 107.7v1.8" fill="none" stroke="#000" stroke-width=".17"/>
<circle cx="285.2" cy="105.8" r=".46" fill="#00f"/>
<circle cx="285.2" cy="105.8" r=".46" fill="none" stroke="#00f" stroke-width=".17"/>
<path d="M283.4 111.4h3.7M283.9 111.9h2.6M284.5 112.5h1.5M285 113.1h.4M285.2 109.5v1.9" fill="none" stroke="#800000" stroke-width=".17"/>
<path d="M275.2 104.6h.7l.4-.4h.7l.4 .4h.8M275.2 106.4h.7l.4-.3h.7l.4 .3h.8M278.2 105.1h-.8l-.4 .3h-.7l-.4-.3h-.7l-1.1 .7M278.2 106.9h-.8l-.4 .4h-.7l-.4-.4h-.7l-1.1 .8" fill="none" stroke="#d0a19e" stroke-width=".17"/>
<path d="M275 104.4h.7l.4-.4h.8l.3 .4h.8M275 106.3h.7l.4-.4h.8l.3 .4h.8M278 104.9h-.8l-.3 .3h-.8l-.4-.3h-.7l-.9 .9M278 106.7h-.8l-.3 .4h-.8l-.4-.4h-.7l-.9 1" fill="none" stroke="#f00" stroke-width=".17"/>
<path d="M227.5 156h48.4v13h-48.4z" fill-rule="evenodd" fill="#fff"/>
<path d="M227.5 156h48.4v13h-48.4z" fill="none" stroke="#38761d" stroke-width=".59"/>
<path d="M195.9 55.6h50.2v5.6h-50.2z" fill-rule="evenodd" fill="#fff"/>
<path d="M195.9 55.6h50.2v5.6h-50.2z" fill="none" stroke="#38761d" stroke-width=".59"/>
<g fill="none" stroke="#800000" stroke-width=".17">
<path d="M93.5 93.7v1.9M93.5 94.6h1.8M19 116v1.9M19 117h1.8M68.3 109.5h1.9M69.3 109.5v1.9M149.3 109.5h1.9M151.2 108.6v1.8M19 123.5v1.8M19 124.4h1.8M68.3 135.6h1.9M69.3 133.7v1.9"/>
<path d="M42.3 157.9h1.8M43.2 157.9v1.8M167 157.9h1.9M167.9 157.9v1.8M206.1 157.9h1.9M207 157.9v1.8M158.6 195.1h3.7M159.2 195.7h2.6M159.7 196.2h1.5M160.3 196.8h.4M160.5 193.2v1.9M167 197h1.9"/>
<path d="M167.9 195.1v1.9M205.2 195.1h3.7M205.7 195.7h2.6M206.3 196.2h1.5M206.8 196.8h.4M207 193.2v1.9"/>
</g>
<path d="M110.2 23.9h1.5M116.2 23.9h1.5M130.7 165.3v1.9M130.7 170.9v1.9M134.4 176.5v1.9M134.4 182.1v1.8" fill="none" stroke="#000" stroke-width=".17"/>
<path d="M111.7 23.2h4.4v1.5h-4.4zM129.2 169.4h3M129.2 168.7h3M130.7 167.2v1.5M130.7 169.4v1.5M133 179.8h2.9M134.4 178.4v1.4M133 180.6h2.9M134.4 180.6v1.5" fill="none" stroke="#00f" stroke-width=".17"/>
<path d="M169.1 186.9l1.4 1.5M170.5 186.9l-1.4 1.5" fill="none" stroke="#f00" stroke-width=".17"/>
<path d="M175.4 161.6h24.2v29.8h-24.2z" fill-rule="evenodd" fill="#ffffb0"/>
<path d="M175.4 161.6h24.2v29.8h-24.2z" fill="none" stroke="#800000" stroke-width=".17"/>
<g fill="none" stroke="#000" stroke-width=".17">
<path d="M169.8 170.9h5.6M169.8 176.5h5.6M169.8 163.5h5.6M179.1 170.9h5.6v2.8l-.9 .9 1.8 1-1.8 .9 1.8 .9-1.8 1 .9 .9v2.8h-5.6M179.1 176.5h2.8M192.6 170h5.7M193.2 166.3h5.1M195.8 168.1h2.5M199.6 170.9h5.6M199.6 176.5h5.6M199.6 167.2h5.6M199.6 172.8h5.6"/>
<path d="M199.6 163.5h5.6M199.6 178.4h5.6M199.6 169h5.6M169.8 182.1h5.6M169.8 189.5h5.6M169.8 187.7h5.6M187.8 183h4.5M199.6 182.1h5.6M199.6 189.5h5.6M199.6 183.9h5.6M199.6 185.8h5.6"/>
</g>
<path d="M214.5 178.4l.9-1h8.4v1.9h-8.4z" fill-rule="evenodd" fill="#ffff80"/>
<path d="M214.5 178.4l.9-1h8.4v1.9h-8.4z" fill="none" stroke="#800000" stroke-width=".17"/>
<path d="M214.5 176.5l.9-.9h8.4v1.8h-8.4z" fill-rule="evenodd" fill="#ffff80"/>
<path d="M214.5 176.5l.9-.9h8.4v1.8h-8.4z" fill="none" stroke="#800000" stroke-width=".17"/>
<path d="M138.1 165.3v1.9M138.1 170.9v1.9" fill="none" stroke="#000" stroke-width=".17"/>
<path d="M136.7 169.4h2.9M136.7 168.7h2.9M138.1 167.2v1.5M138.1 169.4v1.5" fill="none" stroke="#00f" stroke-width=".17"/>
<path d="M35.7 50h14.9v22.3h-14.9z" fill-rule="evenodd" fill="#ffffb0"/>
<path d="M35.7 50h14.9v22.3h-14.9z" fill="none" stroke="#800000" stroke-width=".17"/>
<g fill="none" stroke="#000" stroke-width=".17">
<path d="M30.2 55.6h5.5M30.2 57.4h5.5M30.2 59.3h5.5M30.2 51.8h5.5M50.6 55.6h5.6M50.6 57.4h5.6M50.6 59.3h5.6M50.6 53.7h5.6M30.2 64.9h5.5M30.2 66.7h5.5M30.2 63h5.5M30.2 70.4h5.5"/>
<path d="M37 63.9h3.3M37 65.8h3.1M50.6 64.9h5.6M50.6 66.7h5.6M50.6 63h5.6M50.6 68.6h5.6"/>
</g>
<path d="M11.5 62.1h6.6l.9 .9-.9 .9h-6.6z" fill-rule="evenodd" fill="#ffff80"/>
<g fill="none" stroke="#800000" stroke-width=".17">
<path d="M27.4 46.3h1.8M28.3 46.3v1.8M11.5 62.1h6.6l.9 .9-.9 .9h-6.6zM26.4 76h3.8M27 76.6h2.6M27.6 77.1h1.4M28.1 77.7h.4M28.3 74.2v1.8M75.8 68.6h1.8M76.7 68.6v1.8M63.7 83.5h3.7M64.2 84h2.6"/>
<path d="M64.8 84.6h1.5M65.3 85.1h.4M65.5 81.6v1.9M71.1 83.5h3.7M71.7 84h2.6M72.2 84.6h1.5M72.8 85.1h.4M73 81.6v1.9"/>
</g>
<path d="M55.5 62.3l1.5 1.4M55.5 64.1l1.5 1.5M55.5 66l1.5 1.5M55.5 67.8l1.5 1.5M57 62.3l-1.5 1.4M57 64.1l-1.5 1.5M57 66l-1.5 1.5M57 67.8l-1.5 1.5" fill="none" stroke="#f00" stroke-width=".17"/>
<path d="M65.5 74.2v1.8M65.5 79.7v1.9M73 74.2v1.8M73 79.7v1.9" fill="none" stroke="#000" stroke-width=".17"/>
<path d="M64.1 78.3h2.9M64.1 77.5h2.9M65.5 76v1.5M65.5 78.3v1.4M71.5 78.3h2.9M71.5 77.5h2.9M73 76v1.5M73 78.3v1.4" fill="none" stroke="#00f" stroke-width=".17"/>
<path d="M50.6 25.8v3.7M210.8 98.4h7.4M192.1 105.8h26.1M210.8 100.2h7.4M216.3 118.8h1.9" fill="none" stroke="#000080" stroke-width=".17"/>
<circle cx="216.3" cy="118.8" r=".37" fill="#000080"/>
<g fill="none" stroke="#000080" stroke-width=".17">
<path d="M251.7 96.5h3.7M251.7 111.4h1.9"/>
<circle cx="216.3" cy="118.8" r=".37"/>
</g>
<circle cx="255.4" cy="96.5" r=".37" fill="#000080"/>
<g fill="none" stroke="#000080" stroke-width=".17">
<path d="M216.3 120.7v1.8"/>
<circle cx="255.4" cy="96.5" r=".37"/>
</g>
<circle cx="216.3" cy="120.7" r=".37" fill="#000080"/>
<g fill="none" stroke="#000080" stroke-width=".17">
<path d="M216.3 94.6v1.9"/>
<circle cx="216.3" cy="120.7" r=".37"/>
</g>
<circle cx="216.3" cy="96.5" r=".37" fill="#000080"/>
<g fill="none" stroke="#000080" stroke-width=".17">
<path d="M261 98.4v1.8h-9.3M266.6 107.7h9.3M257.3 137.4v1.9"/>
<circle cx="216.3" cy="96.5" r=".37"/>
</g>
<circle cx="257.3" cy="137.4" r=".37" fill="#000080"/>
<g fill="none" stroke="#000080" stroke-width=".17">
<path d="M246.1 137.4h-5.6v1.9"/>
<circle cx="257.3" cy="137.4" r=".37"/>
</g>
<circle cx="246.1" cy="137.4" r=".37" fill="#000080"/>
<g fill="none" stroke="#000080" stroke-width=".17">
<path d="M251.7 137.4h-5.6v1.9"/>
<circle cx="246.1" cy="137.4" r=".37"/>
</g>
<circle cx="246.1" cy="137.4" r=".37" fill="#000080"/>
<circle cx="246.1" cy="137.4" r=".37" fill="none" stroke="#000080" stroke-width=".17"/>
<circle cx="251.7" cy="137.4" r=".37" fill="#000080"/>
<g fill="none" stroke="#000080" stroke-width=".17">
<path d="M87.9 23.9h7.4M106.5 33.2v1.9M125.1 20.2v5.6M125.1 33.2v1.9M173.5 20.2h52.1M212.6 33.2v1.9M220.1 33.2v1.9M233.1 22.1h13M229.4 135.6v3.7"/>
<circle cx="251.7" cy="137.4" r=".37"/>
</g>
<circle cx="125.1" cy="20.2" r=".37" fill="#000080"/>
<g fill="none" stroke="#000080" stroke-width=".17">
<path d="M212.6 23.9v1.9"/>
<circle cx="125.1" cy="20.2" r=".37"/>
</g>
<circle cx="212.6" cy="23.9" r=".38" fill="#000080"/>
<g fill="none" stroke="#000080" stroke-width=".17">
<path d="M166.1 118.8v1.9"/>
<circle cx="212.6" cy="23.9" r=".38"/>
</g>
<circle cx="166.1" cy="118.8" r=".37" fill="#000080"/>
<g fill="none" stroke="#000080" stroke-width=".17">
<path d="M86 122.5h1.9v16.8h-7.5"/>
<circle cx="166.1" cy="118.8" r=".37"/>
</g>
<circle cx="87.9" cy="122.5" r=".37" fill="#000080"/>
<g fill="none" stroke="#000080" stroke-width=".17">
<path d="M154.9 118.8h1.9"/>
<circle cx="87.9" cy="122.5" r=".37"/>
</g>
<circle cx="154.9" cy="118.8" r=".37" fill="#000080"/>
<g fill="none" stroke="#000080" stroke-width=".17">
<path d="M93.5 163.5v1.8"/>
<circle cx="154.9" cy="118.8" r=".37"/>
</g>
<circle cx="93.5" cy="163.5" r=".37" fill="#000080"/>
<g fill="none" stroke="#000080" stroke-width=".17">
<path d="M100.9 163.5v1.8"/>
<circle cx="93.5" cy="163.5" r=".37"/>
</g>
<circle cx="100.9" cy="163.5" r=".37" fill="#000080"/>
<g fill="none" stroke="#000080" stroke-width=".17">
<path d="M48.8 139.3v1.8M108.4 163.5v1.8"/>
<circle cx="100.9" cy="163.5" r=".37"/>
</g>
<circle cx="108.4" cy="163.5" r=".37" fill="#000080"/>
<g fill="none" stroke="#000080" stroke-width=".17">
<path d="M78.6 105.8h1.8M87.9 122.5h1.8M154.9 144.9v1.8"/>
<circle cx="108.4" cy="163.5" r=".37"/>
</g>
<circle cx="87.9" cy="122.5" r=".37" fill="#000080"/>
<g fill="none" stroke="#000080" stroke-width=".17">
<path d="M141.9 109.5h1.8v3.7M104.6 122.5v11.2M136.3 131.8v1.9"/>
<circle cx="87.9" cy="122.5" r=".37"/>
</g>
<circle cx="143.7" cy="109.5" r=".37" fill="#000080"/>
<circle cx="143.7" cy="109.5" r=".37" fill="none" stroke="#000080" stroke-width=".17"/>
<circle cx="143.7" cy="113.2" r=".37" fill="#000080"/>
<g fill="none" stroke="#000080" stroke-width=".17">
<path d="M102.8 100.2h1.8"/>
<circle cx="143.7" cy="113.2" r=".37"/>
</g>
<circle cx="102.8" cy="100.2" r=".37" fill="#000080"/>
<g fill="none" stroke="#000080" stroke-width=".17">
<path d="M102.8 98.4h1.8"/>
<circle cx="102.8" cy="100.2" r=".37"/>
</g>
<circle cx="102.8" cy="98.4" r=".37" fill="#000080"/>
<g fill="none" stroke="#000080" stroke-width=".17">
<path d="M99 122.5v1.9"/>
<circle cx="102.8" cy="98.4" r=".37"/>
</g>
<circle cx="99" cy="122.5" r=".37" fill="#000080"/>
<g fill="none" stroke="#000080" stroke-width=".17">
<path d="M93.5 105.8v3.7h1.8M102.8 109.5h1.8M99 131.8v1.9"/>
<circle cx="99" cy="122.5" r=".37"/>
</g>
<circle cx="93.5" cy="105.8" r=".37" fill="#000080"/>
<g fill="none" stroke="#000080" stroke-width=".17">
<path d="M134.4 113.2h9.3v3.8h-9.3M134.4 122.5h1.9v1.9"/>
<circle cx="93.5" cy="105.8" r=".37"/>
</g>
<circle cx="143.7" cy="117" r=".37" fill="#000080"/>
<circle cx="143.7" cy="117" r=".37" fill="none" stroke="#000080" stroke-width=".17"/>
<circle cx="143.7" cy="113.2" r=".37" fill="#000080"/>
<g fill="none" stroke="#000080" stroke-width=".17">
<path d="M143.7 117v1.8"/>
<circle cx="143.7" cy="113.2" r=".37"/>
</g>
<circle cx="143.7" cy="118.8" r=".37" fill="#000080"/>
<circle cx="143.7" cy="118.8" r=".37" fill="none" stroke="#000080" stroke-width=".17"/>
<circle cx="143.7" cy="117" r=".37" fill="#000080"/>
<g fill="none" stroke="#000080" stroke-width=".17">
<path d="M104.6 113.2h-5.6v9.3h-1.8"/>
<circle cx="143.7" cy="117" r=".37"/>
</g>
<circle cx="99" cy="122.5" r=".37" fill="#000080"/>
<g fill="none" stroke="#000080" stroke-width=".17">
<path d="M22.7 176.5v1.9M22.7 185.8v1.9"/>
<circle cx="99" cy="122.5" r=".37"/>
</g>
<circle cx="22.7" cy="176.5" r=".37" fill="#000080"/>
<g fill="none" stroke="#000080" stroke-width=".17">
<path d="M154.9 122.5h-5.6v22.4h-89.4v-5.6h13.1"/>
<circle cx="22.7" cy="176.5" r=".37"/>
</g>
<circle cx="154.9" cy="122.5" r=".37" fill="#000080"/>
<circle cx="154.9" cy="122.5" r=".37" fill="none" stroke="#000080" stroke-width=".17"/>
<circle cx="59.9" cy="139.3" r=".37" fill="#000080"/>
<g fill="none" stroke="#000080" stroke-width=".17">
<path d="M59.9 126.3v13"/>
<circle cx="59.9" cy="139.3" r=".37"/>
</g>
<circle cx="59.9" cy="139.3" r=".37" fill="#000080"/>
<g fill="none" stroke="#000080" stroke-width=".17">
<path d="M134.4 118.8h9.3v1.9h-9.3"/>
<circle cx="59.9" cy="139.3" r=".37"/>
</g>
<circle cx="143.7" cy="118.8" r=".37" fill="#000080"/>
<g fill="none" stroke="#000080" stroke-width=".17">
<path d="M115.8 163.5h7.4v1.8"/>
<circle cx="143.7" cy="118.8" r=".37"/>
</g>
<circle cx="115.8" cy="163.5" r=".37" fill="#000080"/>
<circle cx="115.8" cy="163.5" r=".37" fill="none" stroke="#000080" stroke-width=".17"/>
<circle cx="123.2" cy="163.5" r=".37" fill="#000080"/>
<g fill="none" stroke="#000080" stroke-width=".17">
<path d="M123.3 172.8v1.8h-7.5"/>
<circle cx="123.2" cy="163.5" r=".37"/>
</g>
<circle cx="115.8" cy="174.6" r=".38" fill="#000080"/>
<circle cx="115.8" cy="174.6" r=".38" fill="none" stroke="#000080" stroke-width=".17"/>
<circle cx="119.5" cy="174.6" r=".37" fill="#000080"/>
<circle cx="119.5" cy="174.6" r=".37" fill="none" stroke="#000080" stroke-width=".17"/>
<circle cx="123.3" cy="174.6" r=".37" fill="#000080"/>
<g fill="none" stroke="#000080" stroke-width=".17">
<path d="M108.4 172.8v1.8"/>
<circle cx="123.3" cy="174.6" r=".37"/>
</g>
<circle cx="108.4" cy="174.6" r=".37" fill="#000080"/>
<g fill="none" stroke="#000080" stroke-width=".17">
<path d="M100.9 172.8v1.8"/>
<circle cx="108.4" cy="174.6" r=".37"/>
</g>
<circle cx="100.9" cy="174.6" r=".37" fill="#000080"/>
<g fill="none" stroke="#000080" stroke-width=".17">
<path d="M93.5 172.8v1.8"/>
<circle cx="100.9" cy="174.6" r=".37"/>
</g>
<circle cx="93.5" cy="174.6" r=".37" fill="#000080"/>
<g fill="none" stroke="#000080" stroke-width=".17">
<path d="M30.2 105.8h18.6"/>
<circle cx="93.5" cy="174.6" r=".37"/>
</g>
<circle cx="48.8" cy="105.8" r=".37" fill="#000080"/>
<g fill="none" stroke="#000080" stroke-width=".17">
<path d="M48.8 115.1v1.9"/>
<circle cx="48.8" cy="105.8" r=".37"/>
</g>
<circle cx="48.8" cy="117" r=".37" fill="#000080"/>
<g fill="none" stroke="#000080" stroke-width=".17">
<path d="M59.9 118.8h-3.7v9.3h-7.4"/>
<circle cx="48.8" cy="117" r=".37"/>
</g>
<circle cx="48.8" cy="128.1" r=".37" fill="#000080"/>
<g fill="none" stroke="#000080" stroke-width=".17">
<path d="M20.8 124.4h1.9M35.7 176.5h1.9M43.2 170.9h13M43.2 180.2v7.5"/>
<circle cx="48.8" cy="128.1" r=".37"/>
</g>
<circle cx="43.2" cy="170.9" r=".37" fill="#000080"/>
<g fill="none" stroke="#000080" stroke-width=".17">
<path d="M45 117h3.8M11.5 120.7h11.2"/>
<circle cx="43.2" cy="170.9" r=".37"/>
</g>
<circle cx="48.8" cy="117" r=".37" fill="#000080"/>
<g fill="none" stroke="#000080" stroke-width=".17">
<path d="M45 124.4h3.8"/>
<circle cx="48.8" cy="117" r=".37"/>
</g>
<circle cx="48.8" cy="124.4" r=".37" fill="#000080"/>
<g fill="none" stroke="#000080" stroke-width=".17">
<path d="M71.1 105.8h-22.3v1.9"/>
<circle cx="48.8" cy="124.4" r=".37"/>
</g>
<circle cx="48.8" cy="105.8" r=".37" fill="#000080"/>
<g fill="none" stroke="#000080" stroke-width=".17">
<path d="M205.2 126.3v1.8"/>
<circle cx="48.8" cy="105.8" r=".37"/>
</g>
<circle cx="205.2" cy="126.3" r=".37" fill="#000080"/>
<g fill="none" stroke="#000080" stroke-width=".17">
<path d="M205.2 126.3h-3.8v1.8"/>
<circle cx="205.2" cy="126.3" r=".37"/>
</g>
<circle cx="205.2" cy="126.3" r=".37" fill="#000080"/>
<g fill="none" stroke="#000080" stroke-width=".17">
<path d="M207 137.4v1.9"/>
<circle cx="205.2" cy="126.3" r=".37"/>
</g>
<circle cx="207" cy="137.4" r=".37" fill="#000080"/>
<g fill="none" stroke="#000080" stroke-width=".17">
<path d="M205.2 23.9v5.6h-7.5"/>
<circle cx="207" cy="137.4" r=".37"/>
</g>
<circle cx="205.2" cy="23.9" r=".37" fill="#000080"/>
<g fill="none" stroke="#000080" stroke-width=".17">
<path d="M20.9 176.5h7.4"/>
<circle cx="205.2" cy="23.9" r=".37"/>
</g>
<circle cx="22.7" cy="176.5" r=".37" fill="#000080"/>
<circle cx="22.7" cy="176.5" r=".37" fill="none" stroke="#000080" stroke-width=".17"/>
<circle cx="24.6" cy="176.5" r=".37" fill="#000080"/>
<g fill="none" stroke="#000080" stroke-width=".17">
<path d="M87.9 105.8h16.7"/>
<circle cx="24.6" cy="176.5" r=".37"/>
</g>
<circle cx="93.5" cy="105.8" r=".37" fill="#000080"/>
<g fill="none" stroke="#000080" stroke-width=".17">
<path d="M210.8 96.5h7.4"/>
<circle cx="93.5" cy="105.8" r=".37"/>
</g>
<circle cx="212.6" cy="96.5" r=".37" fill="#000080"/>
<circle cx="212.6" cy="96.5" r=".37" fill="none" stroke="#000080" stroke-width=".17"/>
<circle cx="216.3" cy="96.5" r=".37" fill="#000080"/>
<g fill="none" stroke="#000080" stroke-width=".17">
<path d="M218.2 117h-1.9v3.7h1.9"/>
<circle cx="216.3" cy="96.5" r=".37"/>
</g>
<circle cx="216.3" cy="118.8" r=".37" fill="#000080"/>
<circle cx="216.3" cy="118.8" r=".37" fill="none" stroke="#000080" stroke-width=".17"/>
<circle cx="216.3" cy="120.7" r=".37" fill="#000080"/>
<g fill="none" stroke="#000080" stroke-width=".17">
<path d="M43.2 169v3.8"/>
<circle cx="216.3" cy="120.7" r=".37"/>
</g>
<circle cx="43.2" cy="170.9" r=".37" fill="#000080"/>
<g fill="none" stroke="#000080" stroke-width=".17">
<path d="M48.8 124.4v7.4"/>
<circle cx="43.2" cy="170.9" r=".37"/>
</g>
<circle cx="48.8" cy="128.1" r=".37" fill="#000080"/>
<circle cx="48.8" cy="128.1" r=".37" fill="none" stroke="#000080" stroke-width=".17"/>
<circle cx="48.8" cy="124.4" r=".37" fill="#000080"/>
<g fill="none" stroke="#000080" stroke-width=".17">
<path d="M190.3 117v1.8"/>
<circle cx="48.8" cy="124.4" r=".37"/>
</g>
<circle cx="190.3" cy="118.8" r=".37" fill="#000080"/>
<g fill="none" stroke="#000080" stroke-width=".17">
<path d="M154.9 105.8v3.7"/>
<circle cx="190.3" cy="118.8" r=".37"/>
</g>
<circle cx="154.9" cy="105.8" r=".37" fill="#000080"/>
<g fill="none" stroke="#000080" stroke-width=".17">
<path d="M205.2 135.6v1.8"/>
<circle cx="154.9" cy="105.8" r=".37"/>
</g>
<circle cx="205.2" cy="137.4" r=".37" fill="#000080"/>
<g fill="none" stroke="#000080" stroke-width=".17">
<path d="M218.2 107.7h-7.4v29.7h-5.6"/>
<circle cx="205.2" cy="137.4" r=".37"/>
</g>
<circle cx="205.2" cy="137.4" r=".37" fill="#000080"/>
<circle cx="205.2" cy="137.4" r=".37" fill="none" stroke="#000080" stroke-width=".17"/>
<circle cx="207" cy="137.4" r=".37" fill="#000080"/>
<circle cx="207" cy="137.4" r=".37" fill="none" stroke="#000080" stroke-width=".17"/>
<circle cx="210.8" cy="111.4" r=".38" fill="#000080"/>
<g fill="none" stroke="#000080" stroke-width=".17">
<path d="M201.4 135.6v1.8"/>
<circle cx="210.8" cy="111.4" r=".38"/>
</g>
<circle cx="201.4" cy="137.4" r=".37" fill="#000080"/>
<g fill="none" stroke="#000080" stroke-width=".17">
<path d="M199.6 137.4h5.6"/>
<circle cx="201.4" cy="137.4" r=".37"/>
</g>
<circle cx="201.4" cy="137.4" r=".37" fill="#000080"/>
<circle cx="201.4" cy="137.4" r=".37" fill="none" stroke="#000080" stroke-width=".17"/>
<circle cx="205.2" cy="137.4" r=".37" fill="#000080"/>
<g fill="none" stroke="#000080" stroke-width=".17">
<path d="M190.3 137.4v1.9"/>
<circle cx="205.2" cy="137.4" r=".37"/>
</g>
<circle cx="190.3" cy="137.4" r=".37" fill="#000080"/>
<g fill="none" stroke="#000080" stroke-width=".17">
<path d="M188.4 137.4h3.7"/>
<circle cx="190.3" cy="137.4" r=".37"/>
</g>
<circle cx="190.3" cy="137.4" r=".37" fill="#000080"/>
<g fill="none" stroke="#000080" stroke-width=".17">
<path d="M261 137.4h-9.3v1.9"/>
<circle cx="190.3" cy="137.4" r=".37"/>
</g>
<circle cx="251.7" cy="137.4" r=".37" fill="#000080"/>
<circle cx="251.7" cy="137.4" r=".37" fill="none" stroke="#000080" stroke-width=".17"/>
<circle cx="257.3" cy="137.4" r=".37" fill="#000080"/>
<g fill="none" stroke="#000080" stroke-width=".17">
<path d="M272.2 135.6v1.8h-3.7"/>
<circle cx="257.3" cy="137.4" r=".37"/>
</g>
<circle cx="270.3" cy="137.4" r=".37" fill="#000080"/>
<g fill="none" stroke="#000080" stroke-width=".17">
<path d="M264.7 92.8h-9.3v5.6h-3.7"/>
<circle cx="270.3" cy="137.4" r=".37"/>
</g>
<circle cx="255.4" cy="96.5" r=".37" fill="#000080"/>
<g fill="none" stroke="#000080" stroke-width=".17">
<path d="M270.3 137.4v1.9"/>
<circle cx="255.4" cy="96.5" r=".37"/>
</g>
<circle cx="270.3" cy="137.4" r=".37" fill="#000080"/>
<g fill="none" stroke="#000080" stroke-width=".17">
<path d="M95.3 94.6h7.5v7.5h1.8"/>
<circle cx="270.3" cy="137.4" r=".37"/>
</g>
<circle cx="102.8" cy="100.2" r=".37" fill="#000080"/>
<circle cx="102.8" cy="100.2" r=".37" fill="none" stroke="#000080" stroke-width=".17"/>
<circle cx="102.8" cy="98.4" r=".37" fill="#000080"/>
<g fill="none" stroke="#000080" stroke-width=".17">
<path d="M20.8 117h1.9M143.7 109.5h5.6M43.2 159.7v1.9"/>
<circle cx="102.8" cy="98.4" r=".37"/>
</g>
<circle cx="143.7" cy="109.5" r=".37" fill="#000080"/>
<g fill="none" stroke="#000080" stroke-width=".17">
<path d="M134.4 105.8h50.3"/>
<circle cx="143.7" cy="109.5" r=".37"/>
</g>
<circle cx="154.9" cy="105.8" r=".37" fill="#000080"/>
<g fill="none" stroke="#000080" stroke-width=".17">
<path d="M154.9 117v9.3"/>
<circle cx="154.9" cy="105.8" r=".37"/>
</g>
<circle cx="154.9" cy="118.8" r=".37" fill="#000080"/>
<circle cx="154.9" cy="118.8" r=".37" fill="none" stroke="#000080" stroke-width=".17"/>
<circle cx="154.9" cy="122.5" r=".37" fill="#000080"/>
<g fill="none" stroke="#000080" stroke-width=".17">
<path d="M220.1 23.9v1.9"/>
<circle cx="154.9" cy="122.5" r=".37"/>
</g>
<circle cx="220.1" cy="23.9" r=".37" fill="#000080"/>
<g fill="none" stroke="#000080" stroke-width=".17">
<path d="M184.7 23.9v5.6h5.6"/>
<circle cx="220.1" cy="23.9" r=".37"/>
</g>
<circle cx="184.7" cy="23.9" r=".37" fill="#000080"/>
<g fill="none" stroke="#000080" stroke-width=".17">
<path d="M251.7 105.8h7.5M251.7 107.7h7.5M266.6 105.8h14.9M74.8 174.6h3.8"/>
<circle cx="184.7" cy="23.9" r=".37"/>
</g>
<circle cx="78.6" cy="174.6" r=".38" fill="#000080"/>
<g fill="none" stroke="#000080" stroke-width=".17">
<path d="M74.8 163.5h3.8"/>
<circle cx="78.6" cy="174.6" r=".38"/>
</g>
<circle cx="78.6" cy="163.5" r=".37" fill="#000080"/>
<g fill="none" stroke="#000080" stroke-width=".17">
<path d="M54.4 22.1h26M106.5 23.9v1.9M136.3 20.2h3.7M147.5 22.1h18.6"/>
<circle cx="78.6" cy="163.5" r=".37"/>
</g>
<circle cx="106.5" cy="23.9" r=".37" fill="#000080"/>
<g fill="none" stroke="#000080" stroke-width=".17">
<path d="M87.9 20.2h40.9"/>
<circle cx="106.5" cy="23.9" r=".37"/>
</g>
<circle cx="125.1" cy="20.2" r=".37" fill="#000080"/>
<g fill="none" stroke="#000080" stroke-width=".17">
<path d="M173.5 23.9h16.8"/>
<circle cx="125.1" cy="20.2" r=".37"/>
</g>
<circle cx="184.7" cy="23.9" r=".37" fill="#000080"/>
<g fill="none" stroke="#000080" stroke-width=".17">
<path d="M102.8 23.9h7.4"/>
<circle cx="184.7" cy="23.9" r=".37"/>
</g>
<circle cx="106.5" cy="23.9" r=".37" fill="#000080"/>
<g fill="none" stroke="#000080" stroke-width=".17">
<path d="M117.7 23.9h22.3M197.7 23.9h27.9"/>
<circle cx="106.5" cy="23.9" r=".37"/>
</g>
<circle cx="205.2" cy="23.9" r=".37" fill="#000080"/>
<circle cx="205.2" cy="23.9" r=".37" fill="none" stroke="#000080" stroke-width=".17"/>
<circle cx="212.6" cy="23.9" r=".38" fill="#000080"/>
<circle cx="212.6" cy="23.9" r=".38" fill="none" stroke="#000080" stroke-width=".17"/>
<circle cx="220.1" cy="23.9" r=".37" fill="#000080"/>
<g fill="none" stroke="#000080" stroke-width=".17">
<path d="M78.6 172.8v1.8h7.4"/>
<circle cx="220.1" cy="23.9" r=".37"/>
</g>
<circle cx="86" cy="174.6" r=".37" fill="#000080"/>
<circle cx="86" cy="174.6" r=".37" fill="none" stroke="#000080" stroke-width=".17"/>
<circle cx="82.3" cy="174.6" r=".38" fill="#000080"/>
<circle cx="82.3" cy="174.6" r=".38" fill="none" stroke="#000080" stroke-width=".17"/>
<circle cx="78.6" cy="174.6" r=".38" fill="#000080"/>
<g fill="none" stroke="#000080" stroke-width=".17">
<path d="M86 172.8v1.8"/>
<circle cx="78.6" cy="174.6" r=".38"/>
</g>
<circle cx="86" cy="174.6" r=".37" fill="#000080"/>
<g fill="none" stroke="#000080" stroke-width=".17">
<path d="M86 163.5v1.8"/>
<circle cx="86" cy="174.6" r=".37"/>
</g>
<circle cx="86" cy="163.5" r=".37" fill="#000080"/>
<g fill="none" stroke="#000080" stroke-width=".17">
<path d="M190.3 120.7v-1.9h14.9v7.5"/>
<circle cx="86" cy="163.5" r=".37"/>
</g>
<circle cx="190.3" cy="118.8" r=".37" fill="#000080"/>
<circle cx="190.3" cy="118.8" r=".37" fill="none" stroke="#000080" stroke-width=".17"/>
<circle cx="205.2" cy="126.3" r=".37" fill="#000080"/>
<g fill="none" stroke="#000080" stroke-width=".17">
<path d="M169.8 117v1.8h-5.6"/>
<circle cx="205.2" cy="126.3" r=".37"/>
</g>
<circle cx="166.1" cy="118.8" r=".37" fill="#000080"/>
<g fill="none" stroke="#000080" stroke-width=".17">
<path d="M78.6 165.3v-1.8h37.2v1.8"/>
<circle cx="166.1" cy="118.8" r=".37"/>
</g>
<circle cx="78.6" cy="163.5" r=".37" fill="#000080"/>
<circle cx="78.6" cy="163.5" r=".37" fill="none" stroke="#000080" stroke-width=".17"/>
<circle cx="86" cy="163.5" r=".37" fill="#000080"/>
<circle cx="86" cy="163.5" r=".37" fill="none" stroke="#000080" stroke-width=".17"/>
<circle cx="93.5" cy="163.5" r=".37" fill="#000080"/>
<circle cx="93.5" cy="163.5" r=".37" fill="none" stroke="#000080" stroke-width=".17"/>
<circle cx="100.9" cy="163.5" r=".37" fill="#000080"/>
<circle cx="100.9" cy="163.5" r=".37" fill="none" stroke="#000080" stroke-width=".17"/>
<circle cx="108.4" cy="163.5" r=".37" fill="#000080"/>
<circle cx="108.4" cy="163.5" r=".37" fill="none" stroke="#000080" stroke-width=".17"/>
<circle cx="115.8" cy="163.5" r=".37" fill="#000080"/>
<g fill="none" stroke="#000080" stroke-width=".17">
<path d="M154.9 135.6h5.6v35.3h9.3"/>
<circle cx="115.8" cy="163.5" r=".37"/>
</g>
<circle cx="154.9" cy="135.6" r=".37" fill="#000080"/>
<g fill="none" stroke="#000080" stroke-width=".17">
<path d="M160.5 182.1h9.3"/>
<circle cx="154.9" cy="135.6" r=".37"/>
</g>
<circle cx="160.5" cy="182.1" r=".37" fill="#000080"/>
<g fill="none" stroke="#000080" stroke-width=".17">
<path d="M167.9 159.7v3.8h1.9M123.2 163.5h7.5v1.8M169.8 189.5h-1.9v5.6"/>
<circle cx="160.5" cy="182.1" r=".37"/>
</g>
<circle cx="123.2" cy="163.5" r=".37" fill="#000080"/>
<circle cx="123.2" cy="163.5" r=".37" fill="none" stroke="#000080" stroke-width=".17"/>
<circle cx="130.7" cy="163.5" r=".37" fill="#000080"/>
<g fill="none" stroke="#000080" stroke-width=".17">
<path d="M130.7 172.8v1.8"/>
<circle cx="130.7" cy="163.5" r=".37"/>
</g>
<circle cx="130.7" cy="174.6" r=".37" fill="#000080"/>
<g fill="none" stroke="#000080" stroke-width=".17">
<path d="M154.9 133.7v3.7"/>
<circle cx="130.7" cy="174.6" r=".37"/>
</g>
<circle cx="154.9" cy="135.6" r=".37" fill="#000080"/>
<g fill="none" stroke="#000080" stroke-width=".17">
<path d="M169.8 176.5h-9.3v16.7"/>
<circle cx="154.9" cy="135.6" r=".37"/>
</g>
<circle cx="160.5" cy="182.1" r=".37" fill="#000080"/>
<g fill="none" stroke="#000080" stroke-width=".17">
<path d="M207 159.7v3.8h-1.8"/>
<circle cx="160.5" cy="182.1" r=".37"/>
</g>
<circle cx="207" cy="163.5" r=".37" fill="#000080"/>
<g fill="none" stroke="#000080" stroke-width=".17">
<path d="M205.2 189.5h1.8v3.7"/>
<circle cx="207" cy="163.5" r=".37"/>
</g>
<circle cx="207" cy="189.5" r=".37" fill="#000080"/>
<g fill="none" stroke="#000080" stroke-width=".17">
<path d="M207 163.5v3.7h-1.8"/>
<circle cx="207" cy="189.5" r=".37"/>
</g>
<circle cx="207" cy="167.2" r=".37" fill="#000080"/>
<circle cx="207" cy="167.2" r=".37" fill="none" stroke="#000080" stroke-width=".17"/>
<circle cx="207" cy="163.5" r=".37" fill="#000080"/>
<g fill="none" stroke="#000080" stroke-width=".17">
<path d="M207 167.2v1.8h-1.8"/>
<circle cx="207" cy="163.5" r=".37"/>
</g>
<circle cx="207" cy="169" r=".37" fill="#000080"/>
<circle cx="207" cy="169" r=".37" fill="none" stroke="#000080" stroke-width=".17"/>
<circle cx="207" cy="167.2" r=".37" fill="#000080"/>
<g fill="none" stroke="#000080" stroke-width=".17">
<path d="M207 169v1.9h-1.8"/>
<circle cx="207" cy="167.2" r=".37"/>
</g>
<circle cx="207" cy="170.9" r=".38" fill="#000080"/>
<circle cx="207" cy="170.9" r=".38" fill="none" stroke="#000080" stroke-width=".17"/>
<circle cx="207" cy="169" r=".37" fill="#000080"/>
<g fill="none" stroke="#000080" stroke-width=".17">
<path d="M207 170.9v1.9h-1.8"/>
<circle cx="207" cy="169" r=".37"/>
</g>
<circle cx="207" cy="170.9" r=".38" fill="#000080"/>
<g fill="none" stroke="#000080" stroke-width=".17">
<path d="M205.2 185.8h1.8v3.7"/>
<circle cx="207" cy="170.9" r=".38"/>
</g>
<circle cx="207" cy="185.8" r=".37" fill="#000080"/>
<circle cx="207" cy="185.8" r=".37" fill="none" stroke="#000080" stroke-width=".17"/>
<circle cx="207" cy="189.5" r=".37" fill="#000080"/>
<g fill="none" stroke="#000080" stroke-width=".17">
<path d="M205.2 182.1h1.8v3.7"/>
<circle cx="207" cy="189.5" r=".37"/>
</g>
<circle cx="207" cy="183.9" r=".37" fill="#000080"/>
<circle cx="207" cy="183.9" r=".37" fill="none" stroke="#000080" stroke-width=".17"/>
<circle cx="207" cy="185.8" r=".37" fill="#000080"/>
<g fill="none" stroke="#000080" stroke-width=".17">
<path d="M205.2 183.9h1.8"/>
<circle cx="207" cy="185.8" r=".37"/>
</g>
<circle cx="207" cy="183.9" r=".37" fill="#000080"/>
<g fill="none" stroke="#000080" stroke-width=".17">
<path d="M138.1 172.8v1.8h-7.4M205.2 176.5h9.3M205.2 178.4h9.3"/>
<circle cx="207" cy="183.9" r=".37"/>
</g>
<circle cx="130.7" cy="174.6" r=".37" fill="#000080"/>
<circle cx="130.7" cy="174.6" r=".37" fill="none" stroke="#000080" stroke-width=".17"/>
<circle cx="134.4" cy="174.6" r=".37" fill="#000080"/>
<g fill="none" stroke="#000080" stroke-width=".17">
<path d="M130.7 163.5h7.4v1.8"/>
<circle cx="134.4" cy="174.6" r=".37"/>
</g>
<circle cx="130.7" cy="163.5" r=".37" fill="#000080"/>
<g fill="none" stroke="#000080" stroke-width=".17">
<path d="M86 174.6h7.5"/>
<circle cx="130.7" cy="163.5" r=".37"/>
</g>
<circle cx="86" cy="174.6" r=".37" fill="#000080"/>
<circle cx="86" cy="174.6" r=".37" fill="none" stroke="#000080" stroke-width=".17"/>
<circle cx="89.7" cy="174.6" r=".37" fill="#000080"/>
<circle cx="89.7" cy="174.6" r=".37" fill="none" stroke="#000080" stroke-width=".17"/>
<circle cx="93.5" cy="174.6" r=".37" fill="#000080"/>
<g fill="none" stroke="#000080" stroke-width=".17">
<path d="M93.5 174.6h7.4"/>
<circle cx="93.5" cy="174.6" r=".37"/>
</g>
<circle cx="93.5" cy="174.6" r=".37" fill="#000080"/>
<circle cx="93.5" cy="174.6" r=".37" fill="none" stroke="#000080" stroke-width=".17"/>
<circle cx="97.2" cy="174.6" r=".37" fill="#000080"/>
<circle cx="97.2" cy="174.6" r=".37" fill="none" stroke="#000080" stroke-width=".17"/>
<circle cx="100.9" cy="174.6" r=".37" fill="#000080"/>
<g fill="none" stroke="#000080" stroke-width=".17">
<path d="M100.9 174.6h7.5"/>
<circle cx="100.9" cy="174.6" r=".37"/>
</g>
<circle cx="100.9" cy="174.6" r=".37" fill="#000080"/>
<circle cx="100.9" cy="174.6" r=".37" fill="none" stroke="#000080" stroke-width=".17"/>
<circle cx="104.6" cy="174.6" r=".37" fill="#000080"/>
<circle cx="104.6" cy="174.6" r=".37" fill="none" stroke="#000080" stroke-width=".17"/>
<circle cx="108.4" cy="174.6" r=".37" fill="#000080"/>
<g fill="none" stroke="#000080" stroke-width=".17">
<path d="M108.4 174.6h7.4"/>
<circle cx="108.4" cy="174.6" r=".37"/>
</g>
<circle cx="108.4" cy="174.6" r=".37" fill="#000080"/>
<circle cx="108.4" cy="174.6" r=".37" fill="none" stroke="#000080" stroke-width=".17"/>
<circle cx="112.1" cy="174.6" r=".38" fill="#000080"/>
<circle cx="112.1" cy="174.6" r=".38" fill="none" stroke="#000080" stroke-width=".17"/>
<circle cx="115.8" cy="174.6" r=".38" fill="#000080"/>
<g fill="none" stroke="#000080" stroke-width=".17">
<path d="M123.3 174.6h7.4"/>
<circle cx="115.8" cy="174.6" r=".38"/>
</g>
<circle cx="123.3" cy="174.6" r=".37" fill="#000080"/>
<circle cx="123.3" cy="174.6" r=".37" fill="none" stroke="#000080" stroke-width=".17"/>
<circle cx="127" cy="174.6" r=".37" fill="#000080"/>
<circle cx="127" cy="174.6" r=".37" fill="none" stroke="#000080" stroke-width=".17"/>
<circle cx="130.7" cy="174.6" r=".37" fill="#000080"/>
<g fill="none" stroke="#000080" stroke-width=".17">
<path d="M82.3 183.9v1.9"/>
<circle cx="130.7" cy="174.6" r=".37"/>
</g>
<circle cx="82.3" cy="185.8" r=".37" fill="#000080"/>
<g fill="none" stroke="#000080" stroke-width=".17">
<path d="M82.3 174.6v1.9"/>
<circle cx="82.3" cy="185.8" r=".37"/>
</g>
<circle cx="82.3" cy="174.6" r=".38" fill="#000080"/>
<g fill="none" stroke="#000080" stroke-width=".17">
<path d="M89.7 183.9v1.9"/>
<circle cx="82.3" cy="174.6" r=".38"/>
</g>
<circle cx="89.7" cy="185.8" r=".37" fill="#000080"/>
<g fill="none" stroke="#000080" stroke-width=".17">
<path d="M89.7 174.6v1.9"/>
<circle cx="89.7" cy="185.8" r=".37"/>
</g>
<circle cx="89.7" cy="174.6" r=".37" fill="#000080"/>
<g fill="none" stroke="#000080" stroke-width=".17">
<path d="M97.2 183.9v1.9"/>
<circle cx="89.7" cy="174.6" r=".37"/>
</g>
<circle cx="97.2" cy="185.8" r=".37" fill="#000080"/>
<g fill="none" stroke="#000080" stroke-width=".17">
<path d="M97.2 174.6v1.9"/>
<circle cx="97.2" cy="185.8" r=".37"/>
</g>
<circle cx="97.2" cy="174.6" r=".37" fill="#000080"/>
<g fill="none" stroke="#000080" stroke-width=".17">
<path d="M104.6 183.9v1.9"/>
<circle cx="97.2" cy="174.6" r=".37"/>
</g>
<circle cx="104.6" cy="185.8" r=".37" fill="#000080"/>
<g fill="none" stroke="#000080" stroke-width=".17">
<path d="M104.6 174.6v1.9"/>
<circle cx="104.6" cy="185.8" r=".37"/>
</g>
<circle cx="104.6" cy="174.6" r=".37" fill="#000080"/>
<g fill="none" stroke="#000080" stroke-width=".17">
<path d="M112.1 183.9v1.9"/>
<circle cx="104.6" cy="174.6" r=".37"/>
</g>
<circle cx="112.1" cy="185.8" r=".37" fill="#000080"/>
<g fill="none" stroke="#000080" stroke-width=".17">
<path d="M112.1 174.6v1.9"/>
<circle cx="112.1" cy="185.8" r=".37"/>
</g>
<circle cx="112.1" cy="174.6" r=".38" fill="#000080"/>
<g fill="none" stroke="#000080" stroke-width=".17">
<path d="M115.8 172.8v1.8"/>
<circle cx="112.1" cy="174.6" r=".38"/>
</g>
<circle cx="115.8" cy="174.6" r=".38" fill="#000080"/>
<g fill="none" stroke="#000080" stroke-width=".17">
<path d="M119.5 183.9v1.9"/>
<circle cx="115.8" cy="174.6" r=".38"/>
</g>
<circle cx="119.5" cy="185.8" r=".37" fill="#000080"/>
<g fill="none" stroke="#000080" stroke-width=".17">
<path d="M119.5 174.6v1.9"/>
<circle cx="119.5" cy="185.8" r=".37"/>
</g>
<circle cx="119.5" cy="174.6" r=".37" fill="#000080"/>
<g fill="none" stroke="#000080" stroke-width=".17">
<path d="M127 183.9v1.9"/>
<circle cx="119.5" cy="174.6" r=".37"/>
</g>
<circle cx="127" cy="185.8" r=".37" fill="#000080"/>
<g fill="none" stroke="#000080" stroke-width=".17">
<path d="M127 174.6v1.9"/>
<circle cx="127" cy="185.8" r=".37"/>
</g>
<circle cx="127" cy="174.6" r=".37" fill="#000080"/>
<g fill="none" stroke="#000080" stroke-width=".17">
<path d="M134.4 174.6v1.9"/>
<circle cx="127" cy="174.6" r=".37"/>
</g>
<circle cx="134.4" cy="174.6" r=".37" fill="#000080"/>
<g fill="none" stroke="#000080" stroke-width=".17">
<path d="M134.4 183.9v1.9h-59.6"/>
<circle cx="134.4" cy="174.6" r=".37"/>
</g>
<circle cx="82.3" cy="185.8" r=".37" fill="#000080"/>
<circle cx="82.3" cy="185.8" r=".37" fill="none" stroke="#000080" stroke-width=".17"/>
<circle cx="89.7" cy="185.8" r=".37" fill="#000080"/>
<circle cx="89.7" cy="185.8" r=".37" fill="none" stroke="#000080" stroke-width=".17"/>
<circle cx="97.2" cy="185.8" r=".37" fill="#000080"/>
<circle cx="97.2" cy="185.8" r=".37" fill="none" stroke="#000080" stroke-width=".17"/>
<circle cx="104.6" cy="185.8" r=".37" fill="#000080"/>
<circle cx="104.6" cy="185.8" r=".37" fill="none" stroke="#000080" stroke-width=".17"/>
<circle cx="112.1" cy="185.8" r=".37" fill="#000080"/>
<circle cx="112.1" cy="185.8" r=".37" fill="none" stroke="#000080" stroke-width=".17"/>
<circle cx="119.5" cy="185.8" r=".37" fill="#000080"/>
<circle cx="119.5" cy="185.8" r=".37" fill="none" stroke="#000080" stroke-width=".17"/>
<circle cx="127" cy="185.8" r=".37" fill="#000080"/>
<g fill="none" stroke="#000080" stroke-width=".17">
<path d="M19 55.6h11.2"/>
<circle cx="127" cy="185.8" r=".37"/>
</g>
<circle cx="20.9" cy="55.6" r=".37" fill="#000080"/>
<g fill="none" stroke="#000080" stroke-width=".17">
<path d="M19 57.4h11.2"/>
<circle cx="20.9" cy="55.6" r=".37"/>
</g>
<circle cx="22.7" cy="57.4" r=".37" fill="#000080"/>
<g fill="none" stroke="#000080" stroke-width=".17">
<path d="M19 63h11.2"/>
<circle cx="22.7" cy="57.4" r=".37"/>
</g>
<circle cx="20.9" cy="63" r=".37" fill="#000080"/>
<g fill="none" stroke="#000080" stroke-width=".17">
<path d="M30.2 70.4h-1.9v3.8"/>
<circle cx="20.9" cy="63" r=".37"/>
</g>
<circle cx="28.3" cy="70.4" r=".37" fill="#000080"/>
<g fill="none" stroke="#000080" stroke-width=".17">
<path d="M28.3 66.7h1.9"/>
<circle cx="28.3" cy="70.4" r=".37"/>
</g>
<circle cx="28.3" cy="66.7" r=".37" fill="#000080"/>
<g fill="none" stroke="#000080" stroke-width=".17">
<path d="M28.3 48.1v3.7h1.9M30.2 59.3h-1.9v5.6"/>
<circle cx="28.3" cy="66.7" r=".37"/>
</g>
<circle cx="28.3" cy="64.9" r=".37" fill="#000080"/>
<g fill="none" stroke="#000080" stroke-width=".17">
<path d="M67.4 31.4h13M87.9 31.4h5.6v7.4h-26.1M153 31.4h13.1M173.5 31.4h5.6v7.4h-26.1M73 72.3v1.9"/>
<circle cx="28.3" cy="64.9" r=".37"/>
</g>
<circle cx="73" cy="72.3" r=".37" fill="#000080"/>
<g fill="none" stroke="#000080" stroke-width=".17">
<path d="M30.2 64.9h-1.9v5.5"/>
<circle cx="73" cy="72.3" r=".37"/>
</g>
<circle cx="28.3" cy="64.9" r=".37" fill="#000080"/>
<circle cx="28.3" cy="64.9" r=".37" fill="none" stroke="#000080" stroke-width=".17"/>
<circle cx="28.3" cy="66.7" r=".37" fill="#000080"/>
<circle cx="28.3" cy="66.7" r=".37" fill="none" stroke="#000080" stroke-width=".17"/>
<circle cx="28.3" cy="70.4" r=".37" fill="#000080"/>
<g fill="none" stroke="#000080" stroke-width=".17">
<path d="M76.7 70.4v1.9h-11.2v1.9"/>
<circle cx="28.3" cy="70.4" r=".37"/>
</g>
<circle cx="73" cy="72.3" r=".37" fill="#000080"/>
<circle cx="73" cy="72.3" r=".37" fill="none" stroke="#000080" stroke-width=".17"/>
<circle cx="20.9" cy="55.6" r=".37" fill="#000080"/>
<circle cx="20.9" cy="55.6" r=".37" fill="none" stroke="#000080" stroke-width=".17"/>
<path d="M20.8 53.7v1.9" fill="none" stroke="#000" stroke-width=".17"/>
<circle cx="20.9" cy="55.6" r=".37" fill="#000080"/>
<circle cx="20.9" cy="55.6" r=".37" fill="none" stroke="#000080" stroke-width=".17"/>
<circle cx="20.8" cy="52.8" r=".93" fill="none" stroke="#000" stroke-width=".17"/>
<circle cx="22.7" cy="57.4" r=".37" fill="#000080"/>
<circle cx="22.7" cy="57.4" r=".37" fill="none" stroke="#000080" stroke-width=".17"/>
<path d="M22.7 57.4v1.9" fill="none" stroke="#000" stroke-width=".17"/>
<circle cx="22.7" cy="57.4" r=".37" fill="#000080"/>
<circle cx="22.7" cy="57.4" r=".37" fill="none" stroke="#000080" stroke-width=".17"/>
<circle cx="22.7" cy="60.2" r=".93" fill="none" stroke="#000" stroke-width=".17"/>
<circle cx="20.9" cy="63" r=".37" fill="#000080"/>
<circle cx="20.9" cy="63" r=".37" fill="none" stroke="#000080" stroke-width=".17"/>
<path d="M20.8 63v1.9" fill="none" stroke="#000" stroke-width=".17"/>
<circle cx="20.9" cy="63" r=".37" fill="#000080"/>
<g fill="none" stroke="#000080" stroke-width=".17">
<path d="M56.2 59.3h1.9M56.2 57.4h1.9M56.2 55.6h1.9M56.2 53.7h1.9M65.5 59.3h13.1M65.5 57.4h13.1M65.5 55.6h13.1M65.5 53.7h13.1"/>
<circle cx="20.9" cy="63" r=".37"/>
</g>
<g fill="none" stroke="#000" stroke-width=".17">
<path d="M58.1 59.3h1.5M58.1 57.4h1.5M58.1 55.6h1.5M58.1 53.7h1.5M64.1 59.3h1.4M64.1 57.4h1.4M64.1 55.6h1.4M64.1 53.7h1.4"/>
<circle cx="20.8" cy="65.8" r=".93"/>
</g>
<path d="M59.6 58.5h4.4v1.5h-4.4zM59.6 56.7h4.4v1.4h-4.4zM59.6 54.8h4.4v1.5h-4.4zM59.6 52.9h4.4v1.5h-4.4z" fill="none" stroke="#00f" stroke-width=".17"/>
<use href="#words"/>
</svg>
